(* Logix 5000 AddOnInstructionDefinition export Banner_T30RKD_Param_v4; software revision 32.00; part 2 of 3 *)
(* tags used below, declared in another part *)
   T30RKD : Banner_T30RKD_v3;
   Port_Data : Banner_IOL_Port_v4;
   Port : DINT;
   Local_Control : DINT;
   Command_Being_Processed : BOOL;
   Update_Archive : BOOL;
   Index_Write_Inprocess : DINT;
   Index_Write_Control : DINT;
   Inprocess_Index : DINT;
(* Banner_T30RKD_Param_v4, continued *)

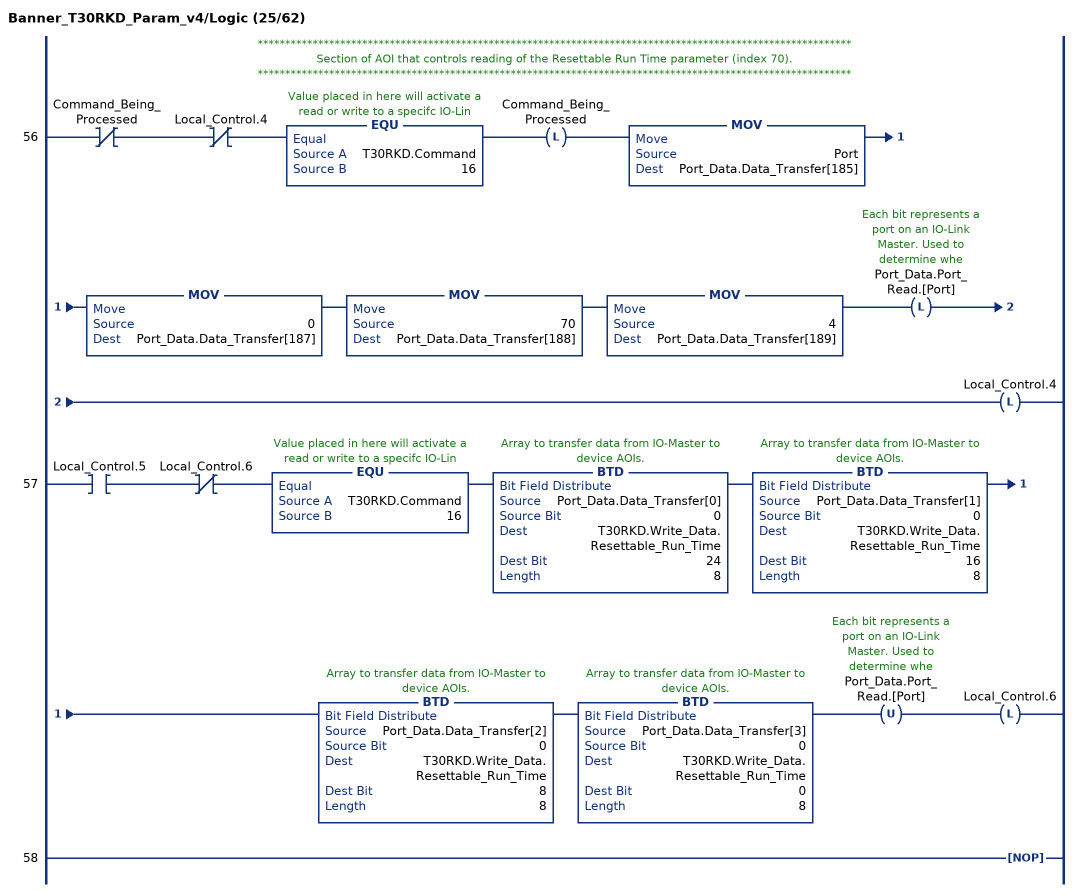
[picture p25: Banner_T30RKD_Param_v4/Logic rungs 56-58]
   // ************************************************************************************************************
   // Section of AOI that controls reading of the Resettable Run Time parameter (index 70).
   // ************************************************************************************************************
   56: XIO(Command_Being_Processed)XIO(Local_Control.4)EQU(T30RKD.Command,16)OTL(Command_Being_Processed)MOV(Port,Port_Data.Data_Transfer[185])MOV(0,Port_Data.Data_Transfer[187])MOV(70,Port_Data.Data_Transfer[188])MOV(4,Port_Data.Data_Transfer[189])OTL(Port_Data.Port_Read.[Port])OTL(Local_Control.4);
   57: XIC(Local_Control.5)XIO(Local_Control.6)EQU(T30RKD.Command,16)BTD(Port_Data.Data_Transfer[0],0,T30RKD.Write_Data.Resettable_Run_Time,24,8)BTD(Port_Data.Data_Transfer[1],0,T30RKD.Write_Data.Resettable_Run_Time,16,8)BTD(Port_Data.Data_Transfer[2],0,T30RKD.Write_Data.Resettable_Run_Time,8,8)BTD(Port_Data.Data_Transfer[3],0,T30RKD.Write_Data.Resettable_Run_Time,0,8)OTU(Port_Data.Port_Read.[Port])OTL(Local_Control.6);
   58: NOP();
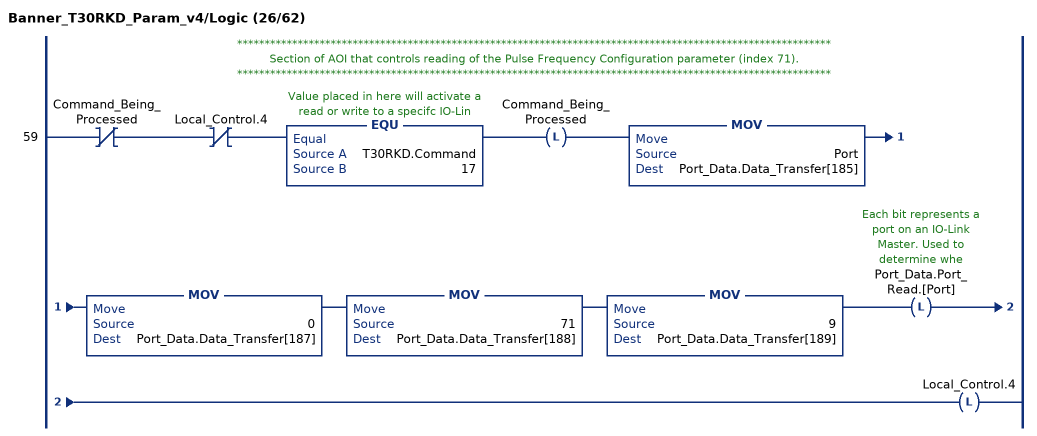
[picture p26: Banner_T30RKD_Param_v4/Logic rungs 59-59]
   // ************************************************************************************************************
   // Section of AOI that controls reading of the Pulse Frequency Configuration parameter (index 71).
   // ************************************************************************************************************
   59: XIO(Command_Being_Processed)XIO(Local_Control.4)EQU(T30RKD.Command,17)OTL(Command_Being_Processed)MOV(Port,Port_Data.Data_Transfer[185])MOV(0,Port_Data.Data_Transfer[187])MOV(71,Port_Data.Data_Transfer[188])MOV(9,Port_Data.Data_Transfer[189])OTL(Port_Data.Port_Read.[Port])OTL(Local_Control.4);
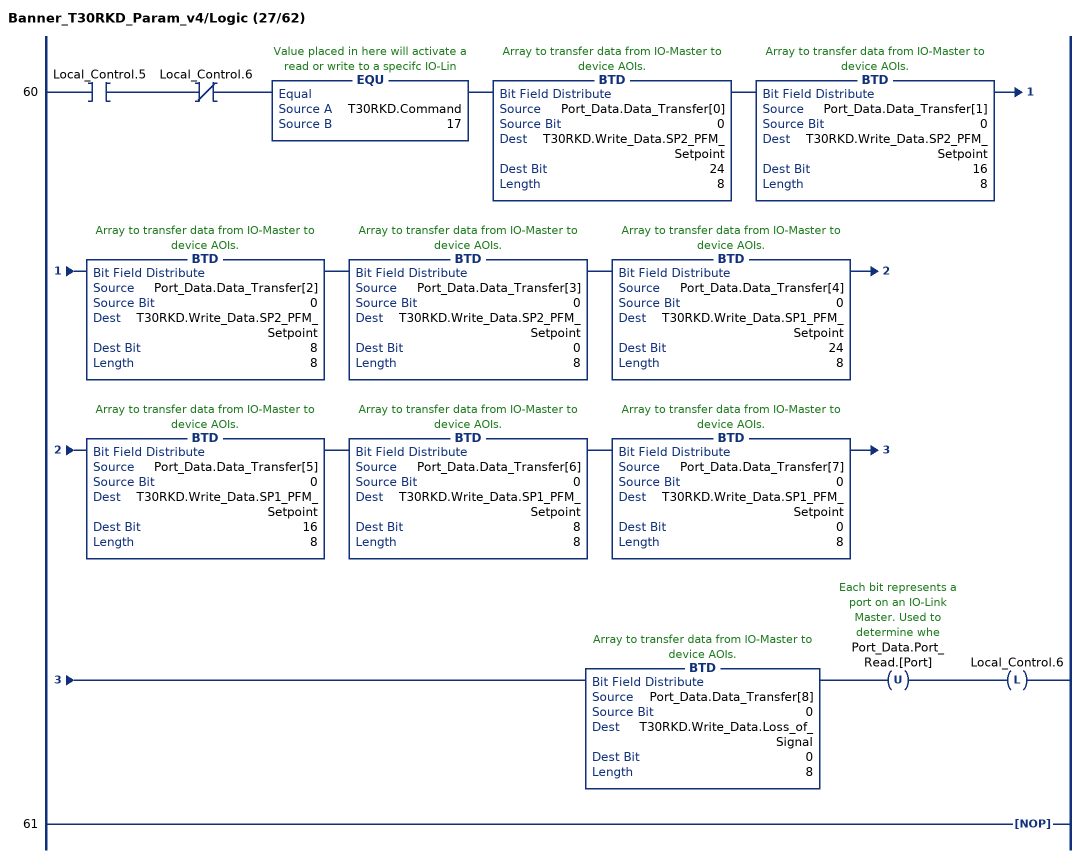
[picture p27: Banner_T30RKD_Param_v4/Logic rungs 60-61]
   60: XIC(Local_Control.5)XIO(Local_Control.6)EQU(T30RKD.Command,17)BTD(Port_Data.Data_Transfer[0],0,T30RKD.Write_Data.SP2_PFM_Setpoint,24,8)BTD(Port_Data.Data_Transfer[1],0,T30RKD.Write_Data.SP2_PFM_Setpoint,16,8)BTD(Port_Data.Data_Transfer[2],0,T30RKD.Write_Data.SP2_PFM_Setpoint,8,8)BTD(Port_Data.Data_Transfer[3],0,T30RKD.Write_Data.SP2_PFM_Setpoint,0,8)BTD(Port_Data.Data_Transfer[4],0,T30RKD.Write_Data.SP1_PFM_Setpoint,24,8)BTD(Port_Data.Data_Transfer[5],0,T30RKD.Write_Data.SP1_PFM_Setpoint,16,8)BTD(Port_Data.Data_Transfer[6],0,T30RKD.Write_Data.SP1_PFM_Setpoint,8,8)BTD(Port_Data.Data_Transfer[7],0,T30RKD.Write_Data.SP1_PFM_Setpoint,0,8)BTD(Port_Data.Data_Transfer[8],0,T30RKD.Write_Data.Loss_of_Signal,0,8)OTU(Port_Data.Port_Read.[Port])OTL(Local_Control.6);
   61: NOP();
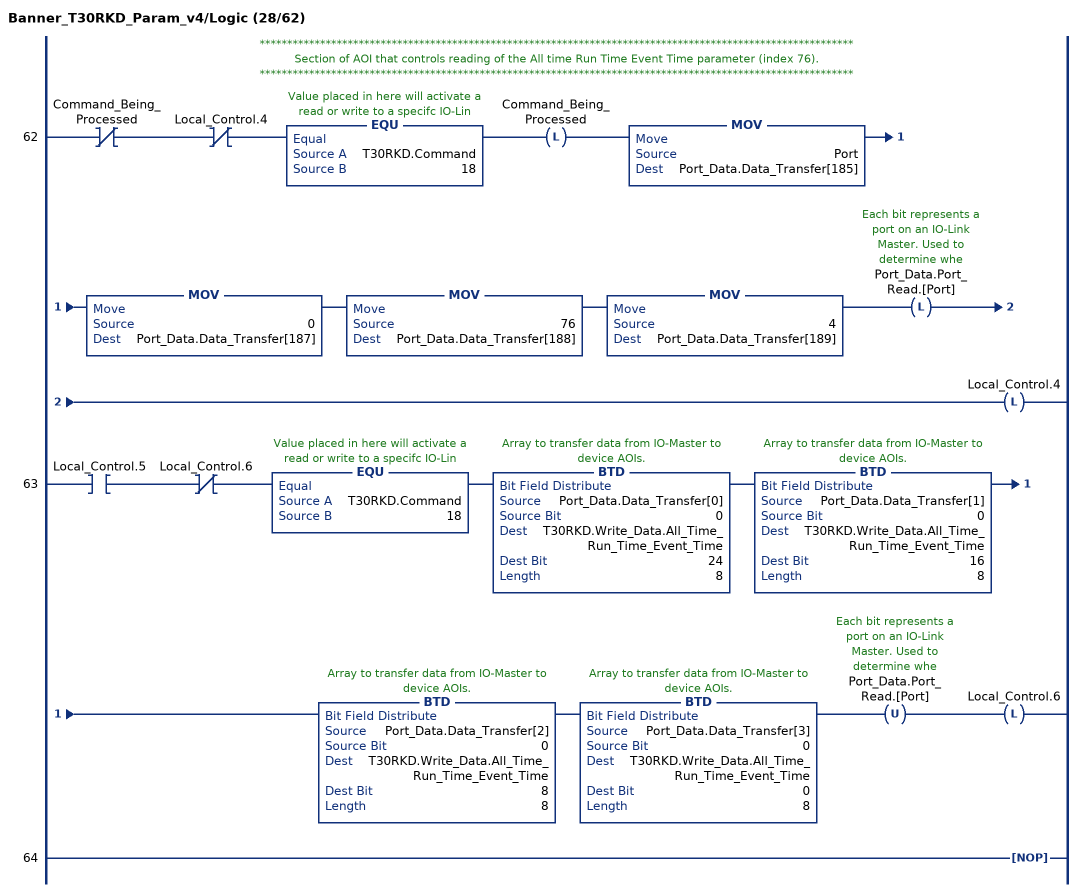
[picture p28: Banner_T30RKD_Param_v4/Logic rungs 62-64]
   // ************************************************************************************************************
   // Section of AOI that controls reading of the All time Run Time Event Time parameter (index 76).
   // ************************************************************************************************************
   62: XIO(Command_Being_Processed)XIO(Local_Control.4)EQU(T30RKD.Command,18)OTL(Command_Being_Processed)MOV(Port,Port_Data.Data_Transfer[185])MOV(0,Port_Data.Data_Transfer[187])MOV(76,Port_Data.Data_Transfer[188])MOV(4,Port_Data.Data_Transfer[189])OTL(Port_Data.Port_Read.[Port])OTL(Local_Control.4);
   63: XIC(Local_Control.5)XIO(Local_Control.6)EQU(T30RKD.Command,18)BTD(Port_Data.Data_Transfer[0],0,T30RKD.Write_Data.All_Time_Run_Time_Event_Time,24,8)BTD(Port_Data.Data_Transfer[1],0,T30RKD.Write_Data.All_Time_Run_Time_Event_Time,16,8)BTD(Port_Data.Data_Transfer[2],0,T30RKD.Write_Data.All_Time_Run_Time_Event_Time,8,8)BTD(Port_Data.Data_Transfer[3],0,T30RKD.Write_Data.All_Time_Run_Time_Event_Time,0,8)OTU(Port_Data.Port_Read.[Port])OTL(Local_Control.6);
   64: NOP();
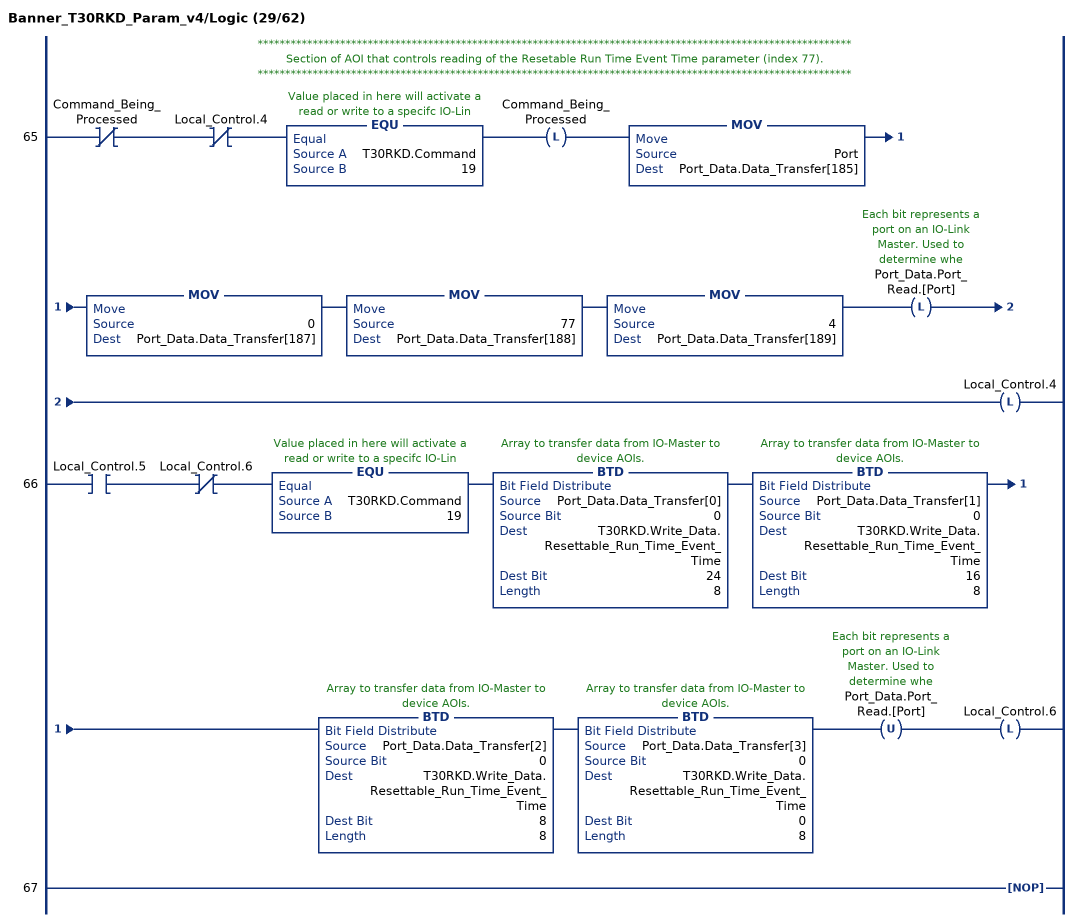
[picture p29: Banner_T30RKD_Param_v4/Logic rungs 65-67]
   // ************************************************************************************************************
   // Section of AOI that controls reading of the Resetable Run Time Event Time parameter (index 77).
   // ************************************************************************************************************
   65: XIO(Command_Being_Processed)XIO(Local_Control.4)EQU(T30RKD.Command,19)OTL(Command_Being_Processed)MOV(Port,Port_Data.Data_Transfer[185])MOV(0,Port_Data.Data_Transfer[187])MOV(77,Port_Data.Data_Transfer[188])MOV(4,Port_Data.Data_Transfer[189])OTL(Port_Data.Port_Read.[Port])OTL(Local_Control.4);
   66: XIC(Local_Control.5)XIO(Local_Control.6)EQU(T30RKD.Command,19)BTD(Port_Data.Data_Transfer[0],0,T30RKD.Write_Data.Resettable_Run_Time_Event_Time,24,8)BTD(Port_Data.Data_Transfer[1],0,T30RKD.Write_Data.Resettable_Run_Time_Event_Time,16,8)BTD(Port_Data.Data_Transfer[2],0,T30RKD.Write_Data.Resettable_Run_Time_Event_Time,8,8)BTD(Port_Data.Data_Transfer[3],0,T30RKD.Write_Data.Resettable_Run_Time_Event_Time,0,8)OTU(Port_Data.Port_Read.[Port])OTL(Local_Control.6);
   67: NOP();
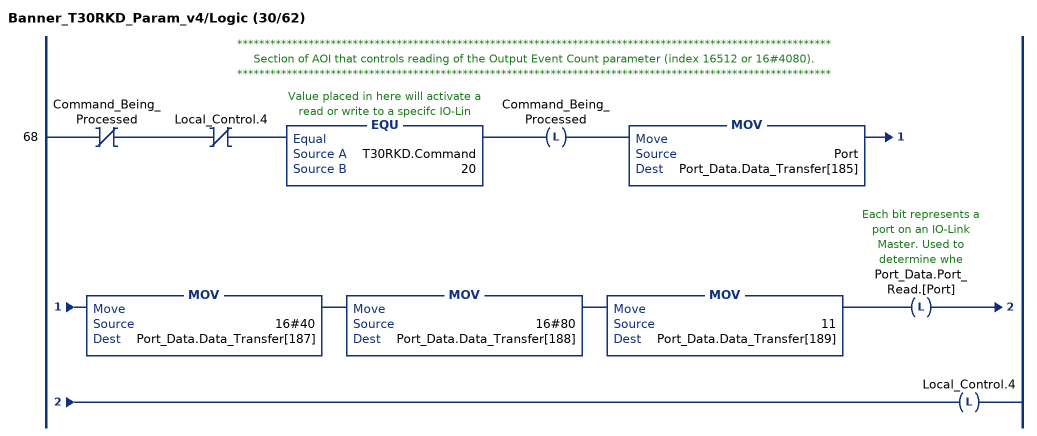
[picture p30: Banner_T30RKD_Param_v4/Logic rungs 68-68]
   // ************************************************************************************************************
   // Section of AOI that controls reading of the Output Event Count parameter (index 16512 or 16#4080).
   // ************************************************************************************************************
   68: XIO(Command_Being_Processed)XIO(Local_Control.4)EQU(T30RKD.Command,20)OTL(Command_Being_Processed)MOV(Port,Port_Data.Data_Transfer[185])MOV(16#40,Port_Data.Data_Transfer[187])MOV(16#80,Port_Data.Data_Transfer[188])MOV(11,Port_Data.Data_Transfer[189])OTL(Port_Data.Port_Read.[Port])OTL(Local_Control.4);
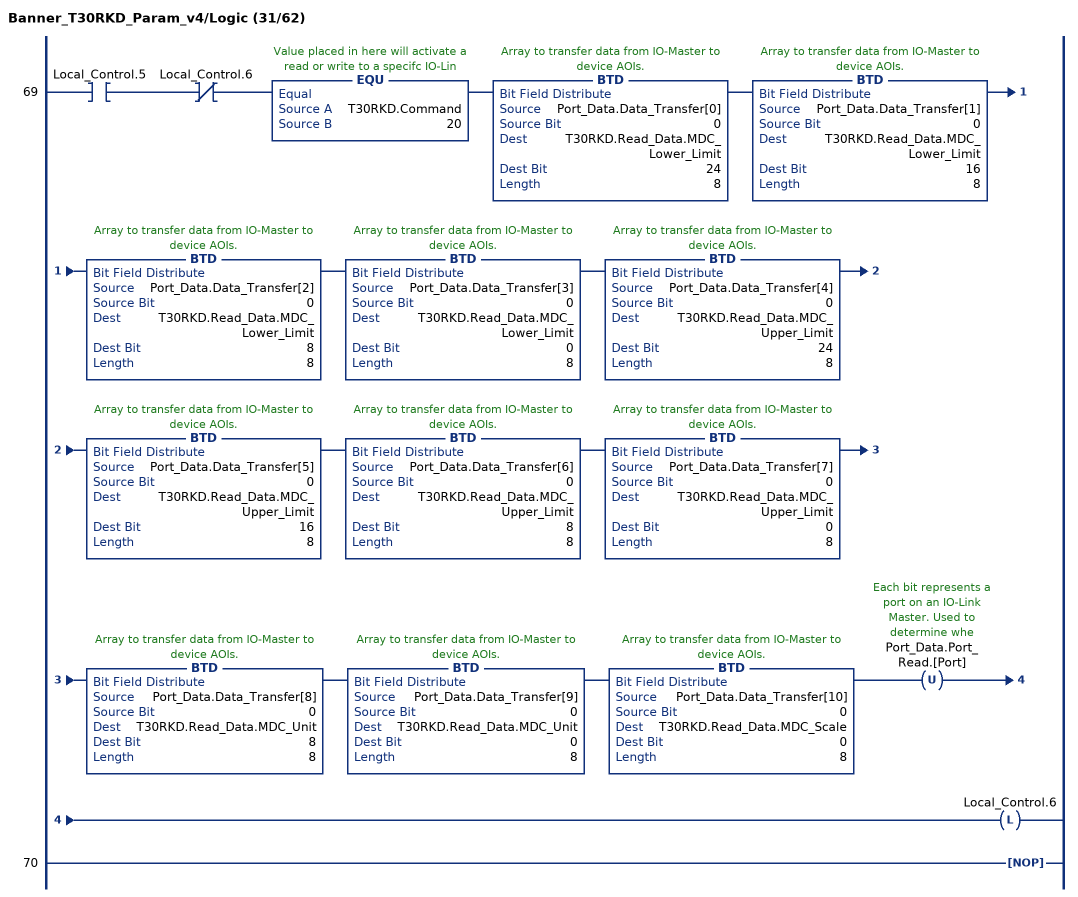
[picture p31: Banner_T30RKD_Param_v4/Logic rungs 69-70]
   69: XIC(Local_Control.5)XIO(Local_Control.6)EQU(T30RKD.Command,20)BTD(Port_Data.Data_Transfer[0],0,T30RKD.Read_Data.MDC_Lower_Limit,24,8)BTD(Port_Data.Data_Transfer[1],0,T30RKD.Read_Data.MDC_Lower_Limit,16,8)BTD(Port_Data.Data_Transfer[2],0,T30RKD.Read_Data.MDC_Lower_Limit,8,8)BTD(Port_Data.Data_Transfer[3],0,T30RKD.Read_Data.MDC_Lower_Limit,0,8)BTD(Port_Data.Data_Transfer[4],0,T30RKD.Read_Data.MDC_Upper_Limit,24,8)BTD(Port_Data.Data_Transfer[5],0,T30RKD.Read_Data.MDC_Upper_Limit,16,8)BTD(Port_Data.Data_Transfer[6],0,T30RKD.Read_Data.MDC_Upper_Limit,8,8)BTD(Port_Data.Data_Transfer[7],0,T30RKD.Read_Data.MDC_Upper_Limit,0,8)BTD(Port_Data.Data_Transfer[8],0,T30RKD.Read_Data.MDC_Unit,8,8)BTD(Port_Data.Data_Transfer[9],0,T30RKD.Read_Data.MDC_Unit,0,8)BTD(Port_Data.Data_Transfer[10],0,T30RKD.Read_Data.MDC_Scale,0,8)OTU(Port_Data.Port_Read.[Port])OTL(Local_Control.6);
   70: NOP();
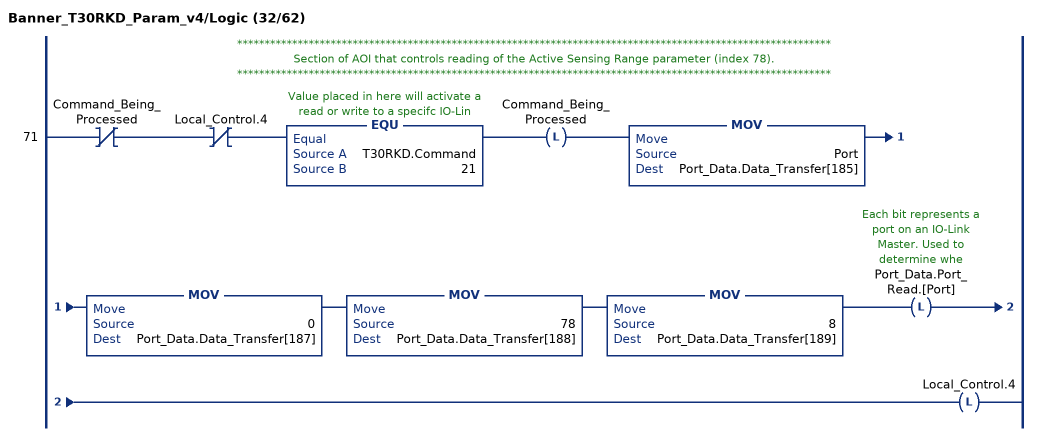
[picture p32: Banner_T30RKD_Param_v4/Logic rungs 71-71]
   // ************************************************************************************************************
   // Section of AOI that controls reading of the Active Sensing Range parameter (index 78).
   // ************************************************************************************************************
   71: XIO(Command_Being_Processed)XIO(Local_Control.4)EQU(T30RKD.Command,21)OTL(Command_Being_Processed)MOV(Port,Port_Data.Data_Transfer[185])MOV(0,Port_Data.Data_Transfer[187])MOV(78,Port_Data.Data_Transfer[188])MOV(8,Port_Data.Data_Transfer[189])OTL(Port_Data.Port_Read.[Port])OTL(Local_Control.4);
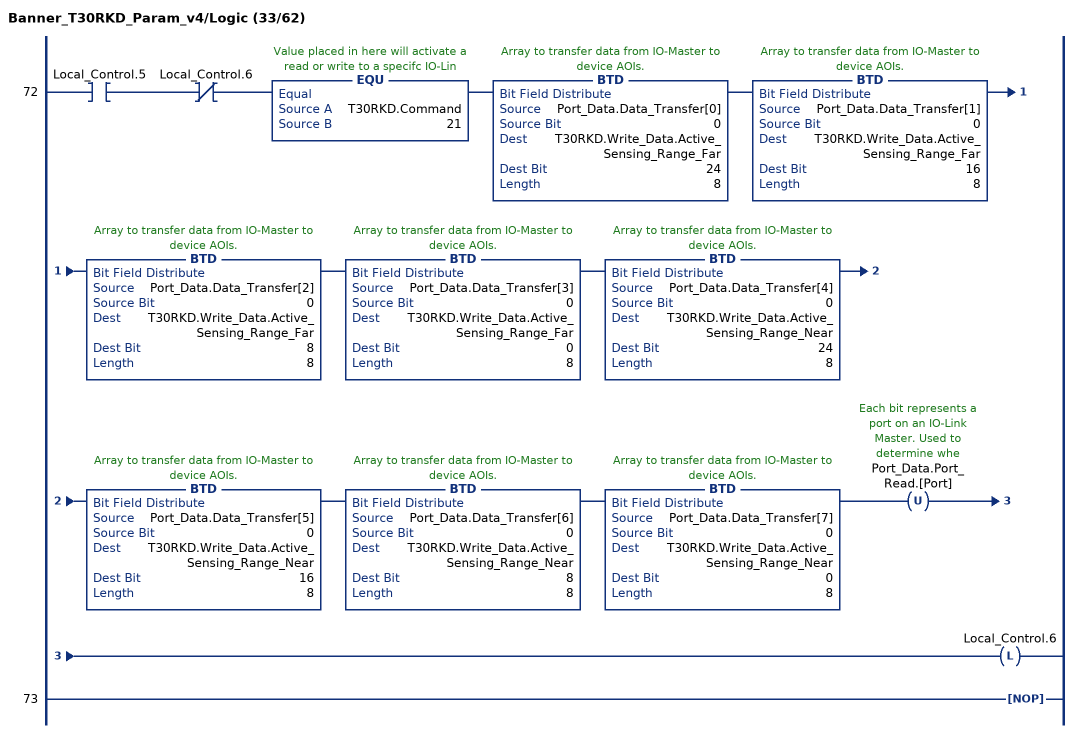
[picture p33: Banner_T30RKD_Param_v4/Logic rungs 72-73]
   72: XIC(Local_Control.5)XIO(Local_Control.6)EQU(T30RKD.Command,21)BTD(Port_Data.Data_Transfer[0],0,T30RKD.Write_Data.Active_Sensing_Range_Far,24,8)BTD(Port_Data.Data_Transfer[1],0,T30RKD.Write_Data.Active_Sensing_Range_Far,16,8)BTD(Port_Data.Data_Transfer[2],0,T30RKD.Write_Data.Active_Sensing_Range_Far,8,8)BTD(Port_Data.Data_Transfer[3],0,T30RKD.Write_Data.Active_Sensing_Range_Far,0,8)BTD(Port_Data.Data_Transfer[4],0,T30RKD.Write_Data.Active_Sensing_Range_Near,24,8)BTD(Port_Data.Data_Transfer[5],0,T30RKD.Write_Data.Active_Sensing_Range_Near,16,8)BTD(Port_Data.Data_Transfer[6],0,T30RKD.Write_Data.Active_Sensing_Range_Near,8,8)BTD(Port_Data.Data_Transfer[7],0,T30RKD.Write_Data.Active_Sensing_Range_Near,0,8)OTU(Port_Data.Port_Read.[Port])OTL(Local_Control.6);
   73: NOP();
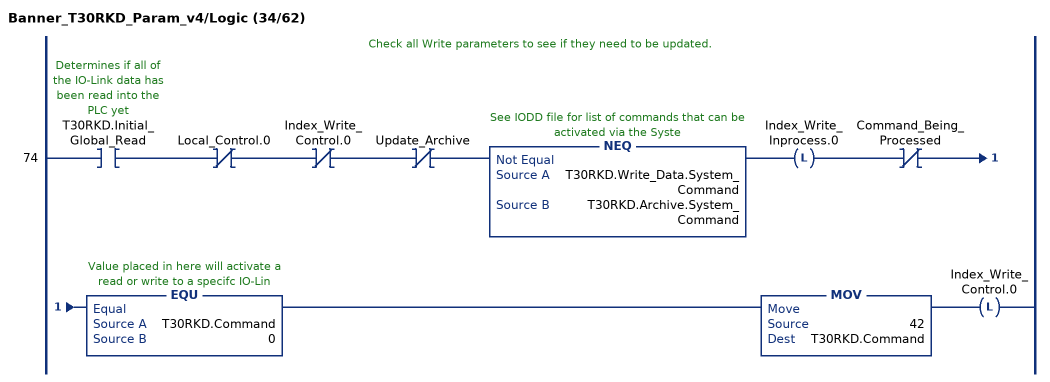
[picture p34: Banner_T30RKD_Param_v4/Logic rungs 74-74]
   // Check all Write parameters to see if they need to be updated.
   74: XIC(T30RKD.Initial_Global_Read)XIO(Local_Control.0)XIO(Index_Write_Control.0)XIO(Update_Archive)NEQ(T30RKD.Write_Data.System_Command,T30RKD.Archive.System_Command)OTL(Index_Write_Inprocess.0)XIO(Command_Being_Processed)EQU(T30RKD.Command,0)MOV(42,T30RKD.Command)OTL(Index_Write_Control.0);
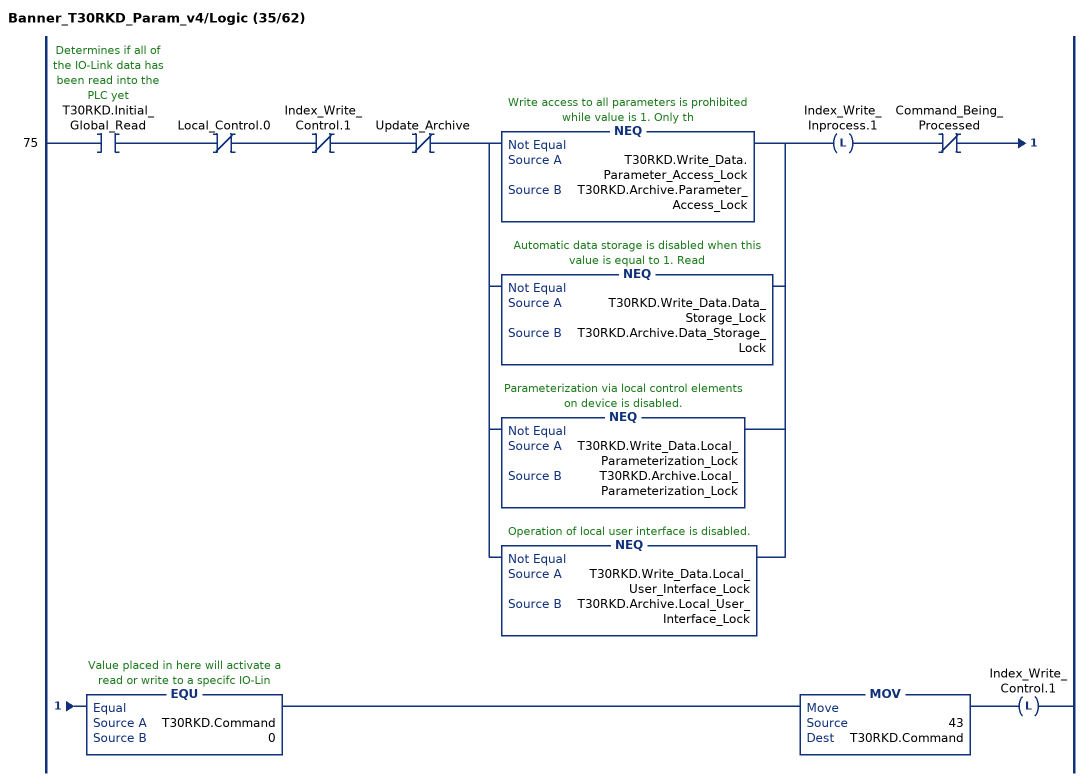
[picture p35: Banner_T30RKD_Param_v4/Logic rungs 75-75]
   75: XIC(T30RKD.Initial_Global_Read)XIO(Local_Control.0)XIO(Index_Write_Control.1)XIO(Update_Archive)[NEQ(T30RKD.Write_Data.Parameter_Access_Lock,T30RKD.Archive.Parameter_Access_Lock) ,NEQ(T30RKD.Write_Data.Data_Storage_Lock,T30RKD.Archive.Data_Storage_Lock) ,NEQ(T30RKD.Write_Data.Local_Parameterization_Lock,T30RKD.Archive.Local_Parameterization_Lock) ,NEQ(T30RKD.Write_Data.Local_User_Interface_Lock,T30RKD.Archive.Local_User_Interface_Lock) ]OTL(Index_Write_Inprocess.1)XIO(Command_Being_Processed)EQU(T30RKD.Command,0)MOV(43,T30RKD.Command)OTL(Index_Write_Control.1);
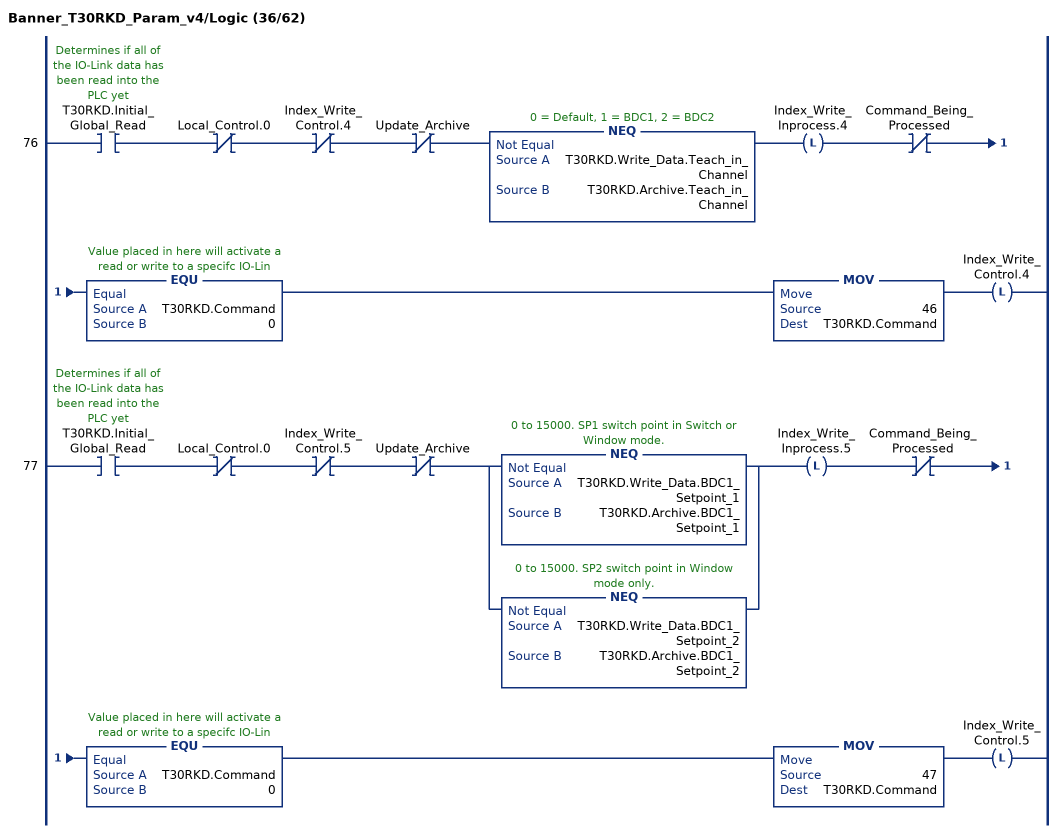
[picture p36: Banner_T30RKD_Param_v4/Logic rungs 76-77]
   76: XIC(T30RKD.Initial_Global_Read)XIO(Local_Control.0)XIO(Index_Write_Control.4)XIO(Update_Archive)NEQ(T30RKD.Write_Data.Teach_in_Channel,T30RKD.Archive.Teach_in_Channel)OTL(Index_Write_Inprocess.4)XIO(Command_Being_Processed)EQU(T30RKD.Command,0)MOV(46,T30RKD.Command)OTL(Index_Write_Control.4);
   77: XIC(T30RKD.Initial_Global_Read)XIO(Local_Control.0)XIO(Index_Write_Control.5)XIO(Update_Archive)[NEQ(T30RKD.Write_Data.BDC1_Setpoint_1,T30RKD.Archive.BDC1_Setpoint_1) ,NEQ(T30RKD.Write_Data.BDC1_Setpoint_2,T30RKD.Archive.BDC1_Setpoint_2) ]OTL(Index_Write_Inprocess.5)XIO(Command_Being_Processed)EQU(T30RKD.Command,0)MOV(47,T30RKD.Command)OTL(Index_Write_Control.5);
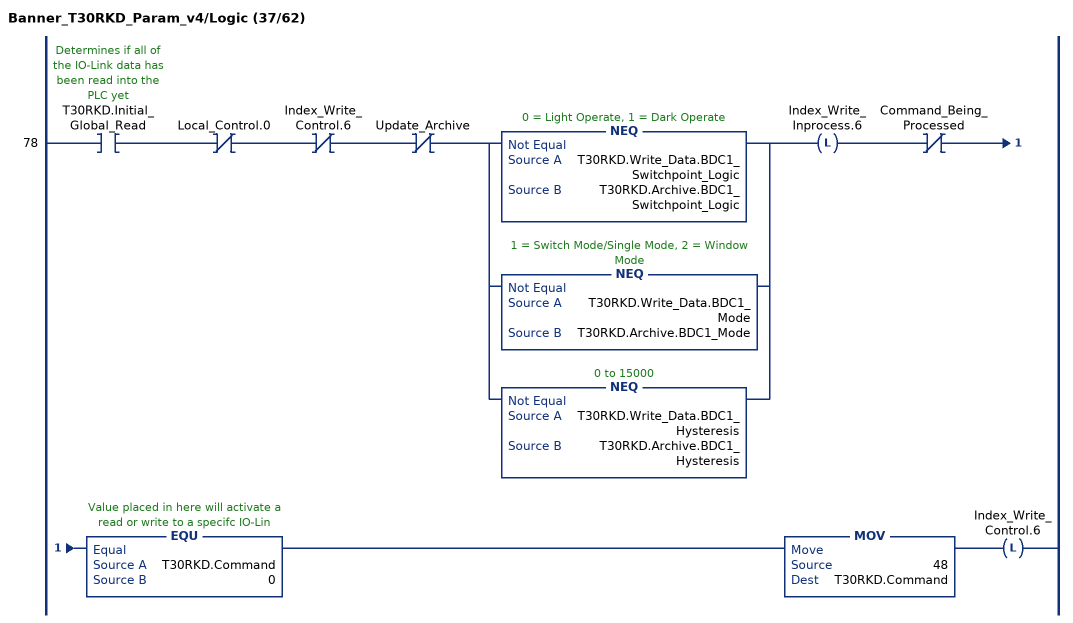
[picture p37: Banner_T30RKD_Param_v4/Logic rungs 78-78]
   78: XIC(T30RKD.Initial_Global_Read)XIO(Local_Control.0)XIO(Index_Write_Control.6)XIO(Update_Archive)[NEQ(T30RKD.Write_Data.BDC1_Switchpoint_Logic,T30RKD.Archive.BDC1_Switchpoint_Logic) ,NEQ(T30RKD.Write_Data.BDC1_Mode,T30RKD.Archive.BDC1_Mode) ,NEQ(T30RKD.Write_Data.BDC1_Hysteresis,T30RKD.Archive.BDC1_Hysteresis) ]OTL(Index_Write_Inprocess.6)XIO(Command_Being_Processed)EQU(T30RKD.Command,0)MOV(48,T30RKD.Command)OTL(Index_Write_Control.6);
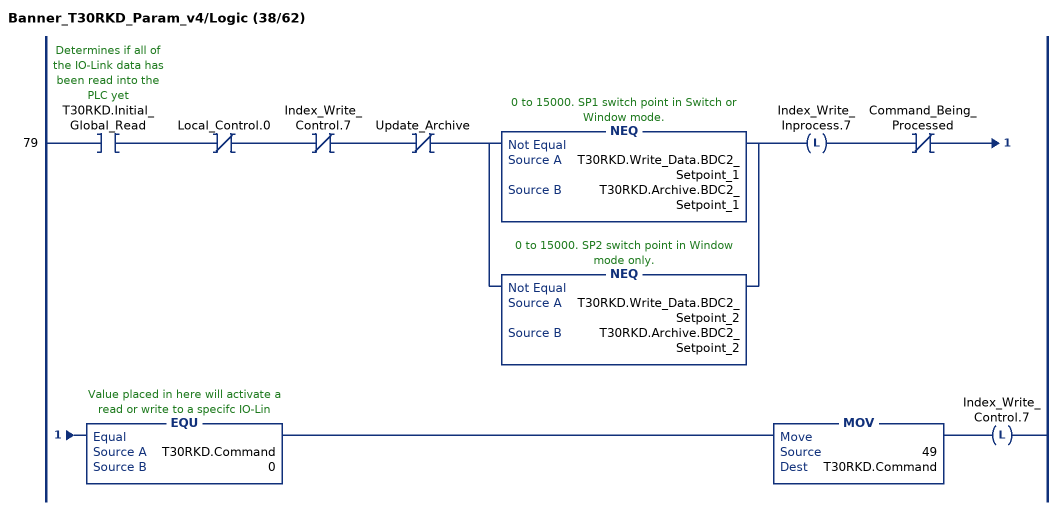
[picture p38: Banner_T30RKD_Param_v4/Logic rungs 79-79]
   79: XIC(T30RKD.Initial_Global_Read)XIO(Local_Control.0)XIO(Index_Write_Control.7)XIO(Update_Archive)[NEQ(T30RKD.Write_Data.BDC2_Setpoint_1,T30RKD.Archive.BDC2_Setpoint_1) ,NEQ(T30RKD.Write_Data.BDC2_Setpoint_2,T30RKD.Archive.BDC2_Setpoint_2) ]OTL(Index_Write_Inprocess.7)XIO(Command_Being_Processed)EQU(T30RKD.Command,0)MOV(49,T30RKD.Command)OTL(Index_Write_Control.7);
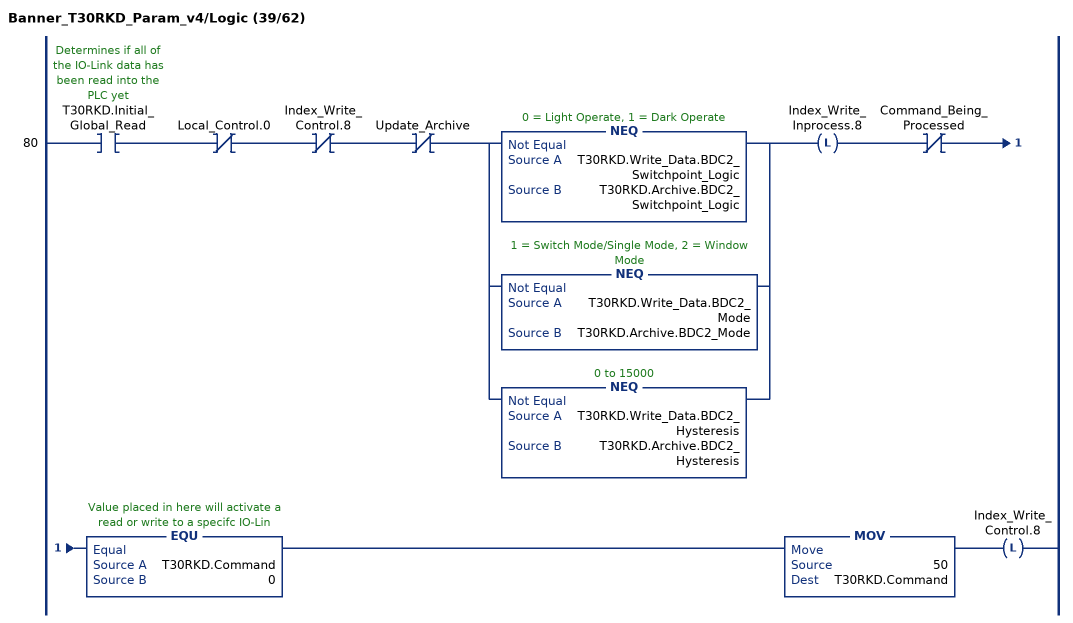
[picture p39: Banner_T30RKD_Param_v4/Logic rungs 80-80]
   80: XIC(T30RKD.Initial_Global_Read)XIO(Local_Control.0)XIO(Index_Write_Control.8)XIO(Update_Archive)[NEQ(T30RKD.Write_Data.BDC2_Switchpoint_Logic,T30RKD.Archive.BDC2_Switchpoint_Logic) ,NEQ(T30RKD.Write_Data.BDC2_Mode,T30RKD.Archive.BDC2_Mode) ,NEQ(T30RKD.Write_Data.BDC2_Hysteresis,T30RKD.Archive.BDC2_Hysteresis) ]OTL(Index_Write_Inprocess.8)XIO(Command_Being_Processed)EQU(T30RKD.Command,0)MOV(50,T30RKD.Command)OTL(Index_Write_Control.8);
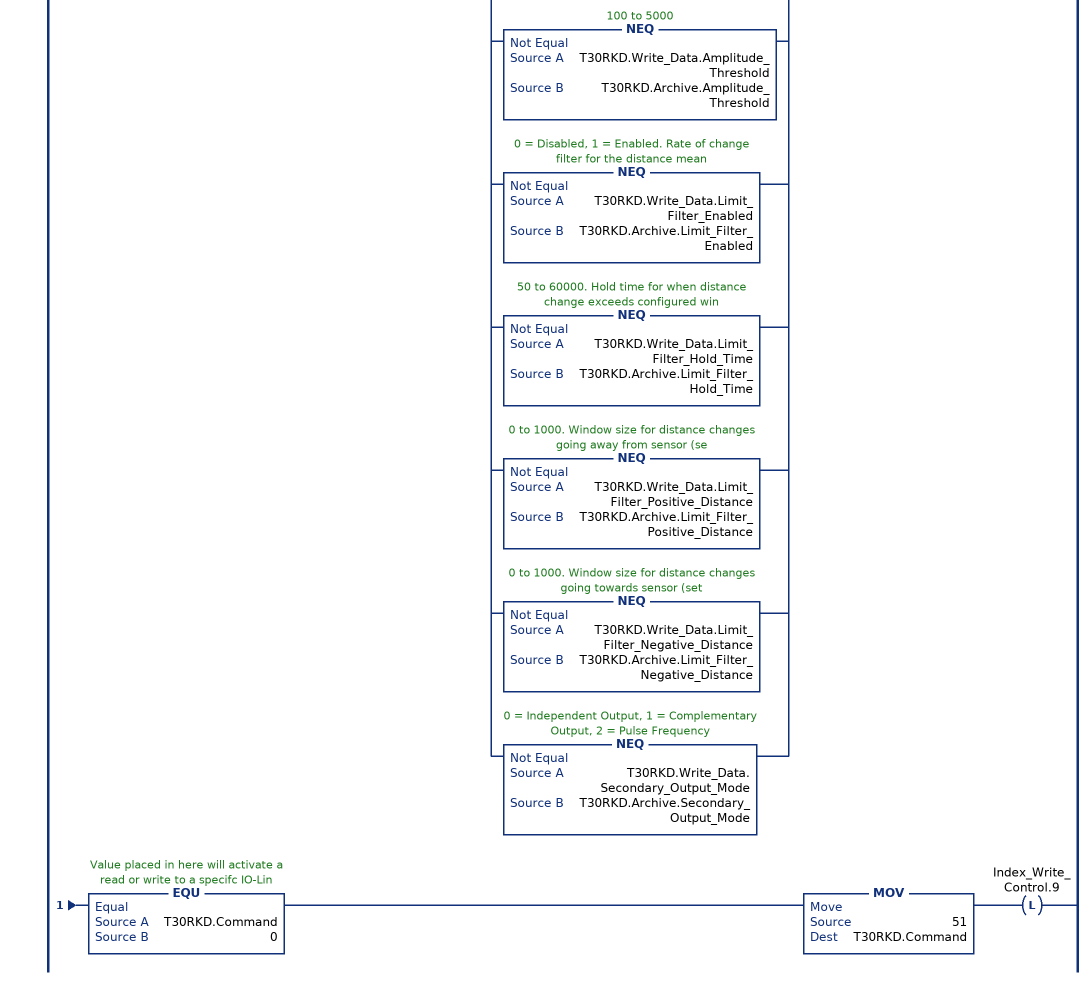
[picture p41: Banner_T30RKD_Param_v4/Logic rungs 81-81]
   81: XIC(T30RKD.Initial_Global_Read)XIO(Local_Control.0)XIO(Index_Write_Control.9)XIO(Update_Archive)[NEQ(T30RKD.Write_Data.Response_Speed,T30RKD.Archive.Response_Speed) ,NEQ(T30RKD.Write_Data.Peak_Select_Mode,T30RKD.Archive.Peak_Select_Mode) ,NEQ(T30RKD.Write_Data.Sensor_Lockout,T30RKD.Archive.Sensor_Lockout) ,NEQ(T30RKD.Write_Data.Output_Polarity,T30RKD.Archive.Output_Polarity) ,NEQ(T30RKD.Write_Data.Process_Data_Filter_Time,T30RKD.Archive.Process_Data_Filter_Time) ,NEQ(T30RKD.Write_Data.Process_Data_Layout,T30RKD.Archive.Process_Data_Layout) ,NEQ(T30RKD.Write_Data.Remote_Input_Mode,T30RKD.Archive.Remote_Input_Mode) ,NEQ(T30RKD.Write_Data.Amplitude_Threshold,T30RKD.Archive.Amplitude_Threshold) ,NEQ(T30RKD.Write_Data.Limit_Filter_Enabled,T30RKD.Archive.Limit_Filter_Enabled) ,NEQ(T30RKD.Write_Data.Limit_Filter_Hold_Time,T30RKD.Archive.Limit_Filter_Hold_Time) ,NEQ(T30RKD.Write_Data.Limit_Filter_Positive_Distance,T30RKD.Archive.Limit_Filter_Positive_Distance) ,NEQ(T30RKD.Write_Data.Limit_Filter_Negative_Distance,T30RKD.Archive.Limit_Filter_Negative_Distance) ,NEQ(T30RKD.Write_Data.Secondary_Output_Mode,T30RKD.Archive.Secondary_Output_Mode) ]OTL(Index_Write_Inprocess.9)XIO(Command_Being_Processed)EQU(T30RKD.Command,0)MOV(51,T30RKD.Command)OTL(Index_Write_Control.9);
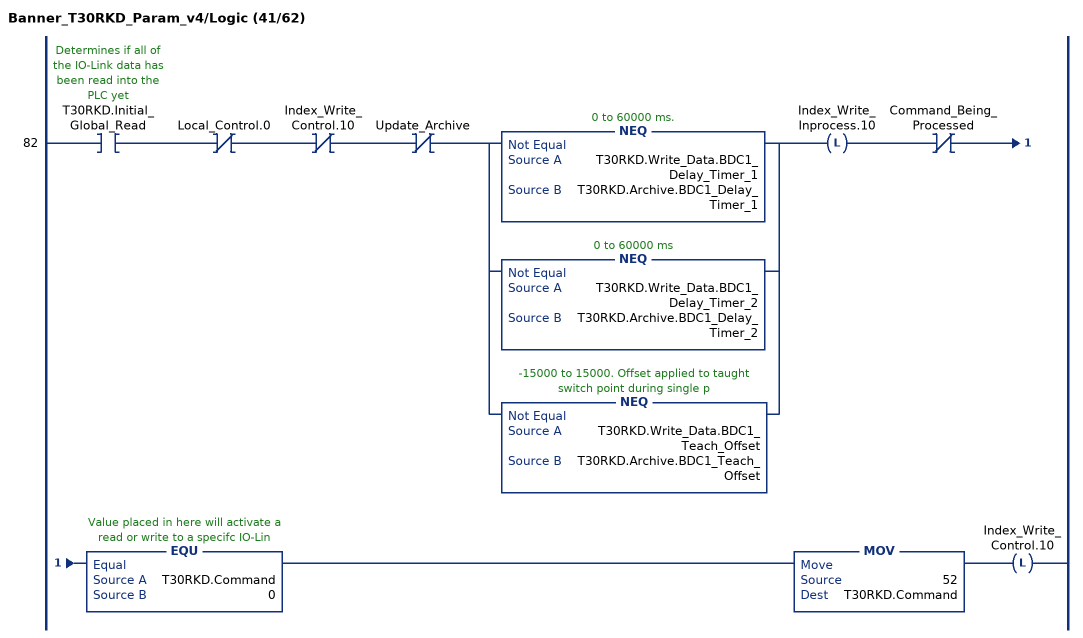
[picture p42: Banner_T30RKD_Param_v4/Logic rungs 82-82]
   82: XIC(T30RKD.Initial_Global_Read)XIO(Local_Control.0)XIO(Index_Write_Control.10)XIO(Update_Archive)[NEQ(T30RKD.Write_Data.BDC1_Delay_Timer_1,T30RKD.Archive.BDC1_Delay_Timer_1) ,NEQ(T30RKD.Write_Data.BDC1_Delay_Timer_2,T30RKD.Archive.BDC1_Delay_Timer_2) ,NEQ(T30RKD.Write_Data.BDC1_Teach_Offset,T30RKD.Archive.BDC1_Teach_Offset) ]OTL(Index_Write_Inprocess.10)XIO(Command_Being_Processed)EQU(T30RKD.Command,0)MOV(52,T30RKD.Command)OTL(Index_Write_Control.10);
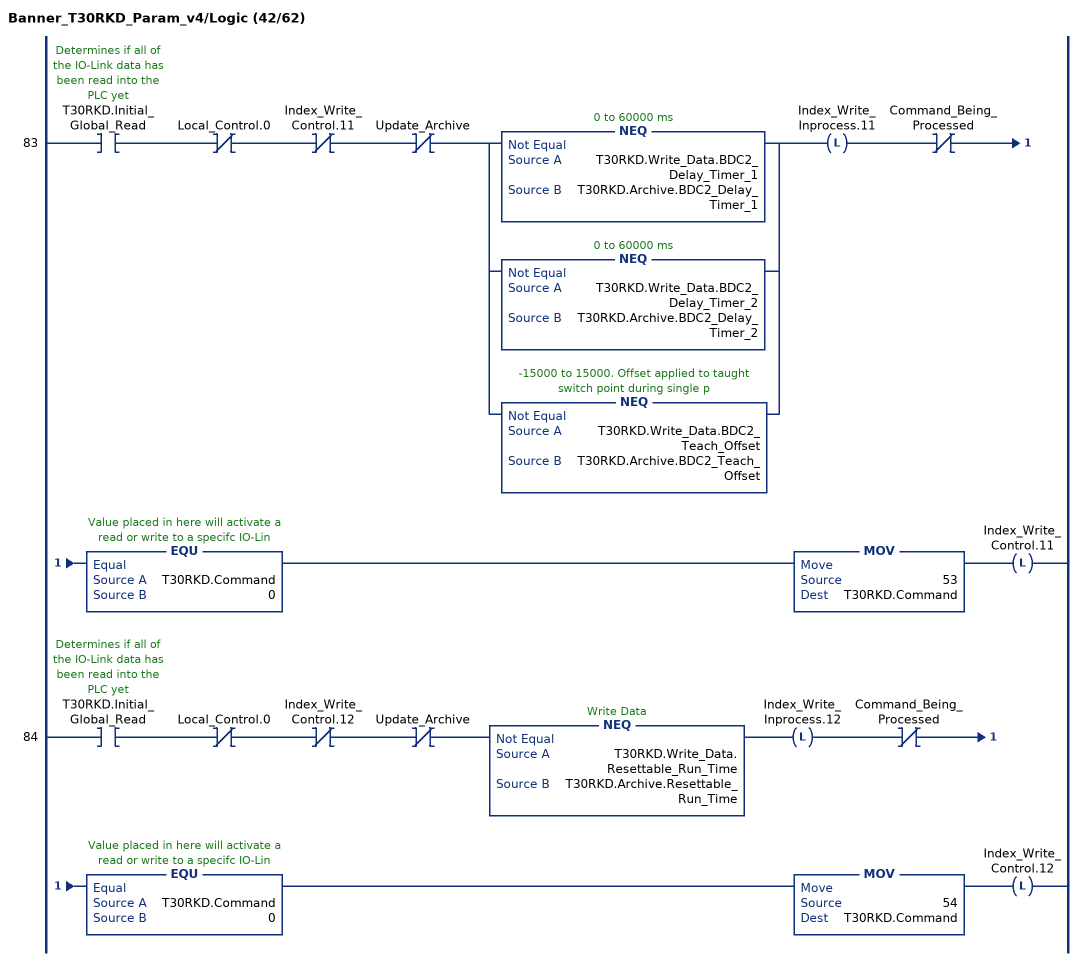
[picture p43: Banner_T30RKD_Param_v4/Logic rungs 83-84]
   83: XIC(T30RKD.Initial_Global_Read)XIO(Local_Control.0)XIO(Index_Write_Control.11)XIO(Update_Archive)[NEQ(T30RKD.Write_Data.BDC2_Delay_Timer_1,T30RKD.Archive.BDC2_Delay_Timer_1) ,NEQ(T30RKD.Write_Data.BDC2_Delay_Timer_2,T30RKD.Archive.BDC2_Delay_Timer_2) ,NEQ(T30RKD.Write_Data.BDC2_Teach_Offset,T30RKD.Archive.BDC2_Teach_Offset) ]OTL(Index_Write_Inprocess.11)XIO(Command_Being_Processed)EQU(T30RKD.Command,0)MOV(53,T30RKD.Command)OTL(Index_Write_Control.11);
   84: XIC(T30RKD.Initial_Global_Read)XIO(Local_Control.0)XIO(Index_Write_Control.12)XIO(Update_Archive)NEQ(T30RKD.Write_Data.Resettable_Run_Time,T30RKD.Archive.Resettable_Run_Time)OTL(Index_Write_Inprocess.12)XIO(Command_Being_Processed)EQU(T30RKD.Command,0)MOV(54,T30RKD.Command)OTL(Index_Write_Control.12);
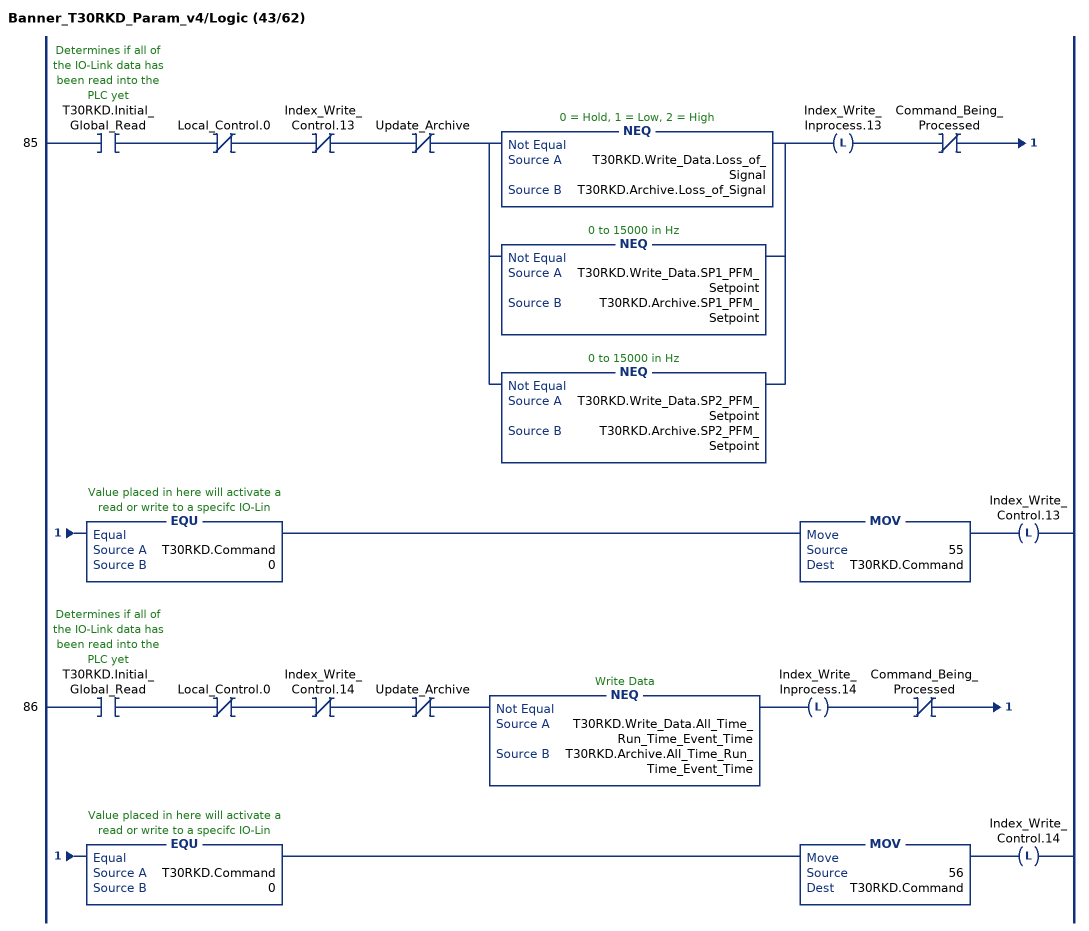
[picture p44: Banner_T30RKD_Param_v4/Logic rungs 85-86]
   85: XIC(T30RKD.Initial_Global_Read)XIO(Local_Control.0)XIO(Index_Write_Control.13)XIO(Update_Archive)[NEQ(T30RKD.Write_Data.Loss_of_Signal,T30RKD.Archive.Loss_of_Signal) ,NEQ(T30RKD.Write_Data.SP1_PFM_Setpoint,T30RKD.Archive.SP1_PFM_Setpoint) ,NEQ(T30RKD.Write_Data.SP2_PFM_Setpoint,T30RKD.Archive.SP2_PFM_Setpoint) ]OTL(Index_Write_Inprocess.13)XIO(Command_Being_Processed)EQU(T30RKD.Command,0)MOV(55,T30RKD.Command)OTL(Index_Write_Control.13);
   86: XIC(T30RKD.Initial_Global_Read)XIO(Local_Control.0)XIO(Index_Write_Control.14)XIO(Update_Archive)NEQ(T30RKD.Write_Data.All_Time_Run_Time_Event_Time,T30RKD.Archive.All_Time_Run_Time_Event_Time)OTL(Index_Write_Inprocess.14)XIO(Command_Being_Processed)EQU(T30RKD.Command,0)MOV(56,T30RKD.Command)OTL(Index_Write_Control.14);
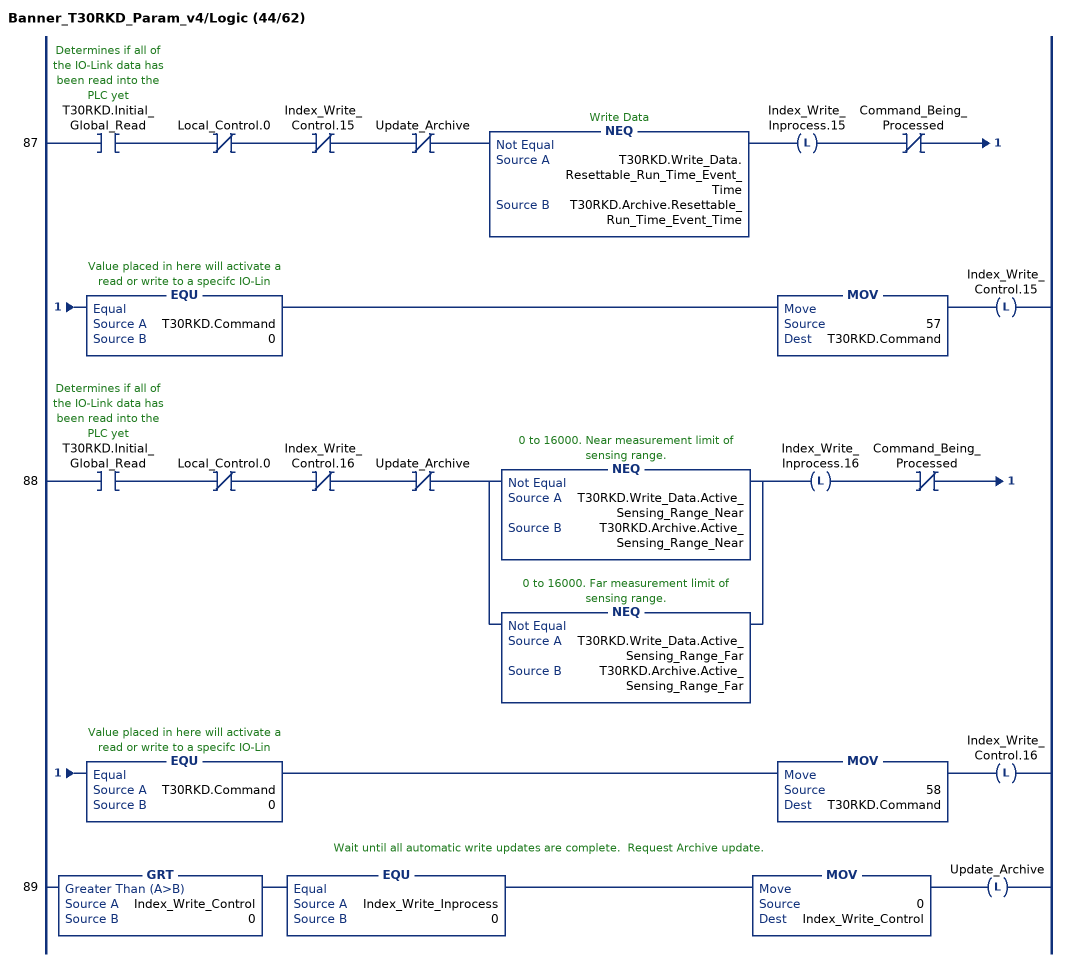
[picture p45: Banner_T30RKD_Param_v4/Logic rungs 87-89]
   87: XIC(T30RKD.Initial_Global_Read)XIO(Local_Control.0)XIO(Index_Write_Control.15)XIO(Update_Archive)NEQ(T30RKD.Write_Data.Resettable_Run_Time_Event_Time,T30RKD.Archive.Resettable_Run_Time_Event_Time)OTL(Index_Write_Inprocess.15)XIO(Command_Being_Processed)EQU(T30RKD.Command,0)MOV(57,T30RKD.Command)OTL(Index_Write_Control.15);
   88: XIC(T30RKD.Initial_Global_Read)XIO(Local_Control.0)XIO(Index_Write_Control.16)XIO(Update_Archive)[NEQ(T30RKD.Write_Data.Active_Sensing_Range_Near,T30RKD.Archive.Active_Sensing_Range_Near) ,NEQ(T30RKD.Write_Data.Active_Sensing_Range_Far,T30RKD.Archive.Active_Sensing_Range_Far) ]OTL(Index_Write_Inprocess.16)XIO(Command_Being_Processed)EQU(T30RKD.Command,0)MOV(58,T30RKD.Command)OTL(Index_Write_Control.16);
   // Wait until all automatic write updates are complete.  Request Archive update.
   89: GRT(Index_Write_Control,0)EQU(Index_Write_Inprocess,0)MOV(0,Index_Write_Control)OTL(Update_Archive);
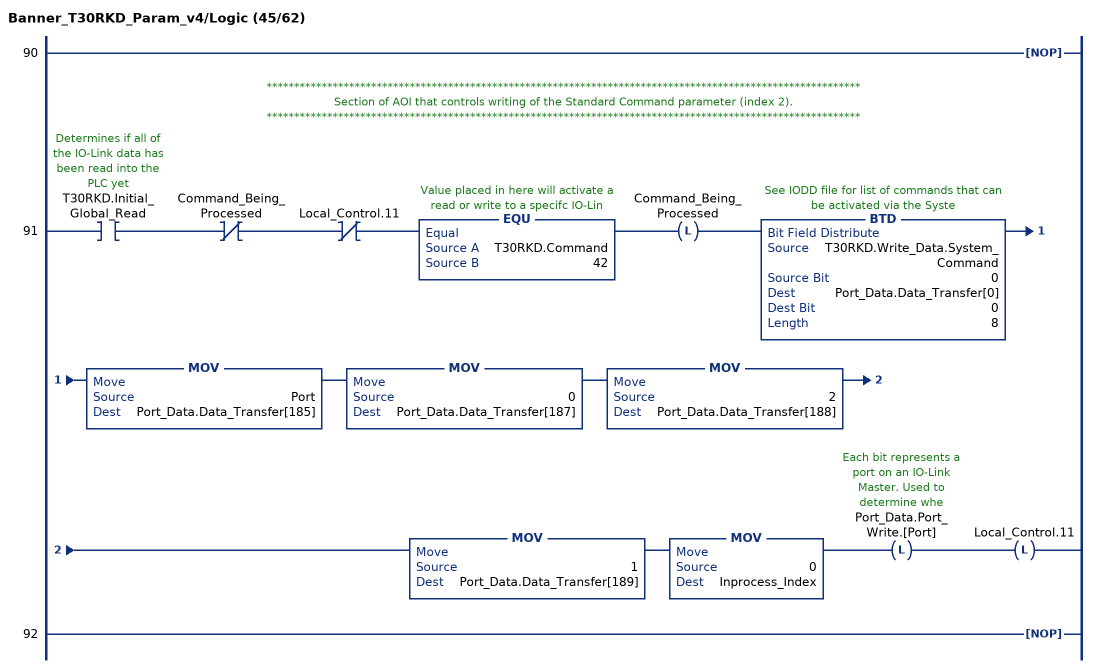
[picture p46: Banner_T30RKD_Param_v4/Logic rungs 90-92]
   90: NOP();
   // ************************************************************************************************************
   // Section of AOI that controls writing of the Standard Command parameter (index 2).
   // ************************************************************************************************************
   91: XIC(T30RKD.Initial_Global_Read)XIO(Command_Being_Processed)XIO(Local_Control.11)EQU(T30RKD.Command,42)OTL(Command_Being_Processed)BTD(T30RKD.Write_Data.System_Command,0,Port_Data.Data_Transfer[0],0,8)MOV(Port,Port_Data.Data_Transfer[185])MOV(0,Port_Data.Data_Transfer[187])MOV(2,Port_Data.Data_Transfer[188])MOV(1,Port_Data.Data_Transfer[189])MOV(0,Inprocess_Index)OTL(Port_Data.Port_Write.[Port])OTL(Local_Control.11);
   92: NOP();
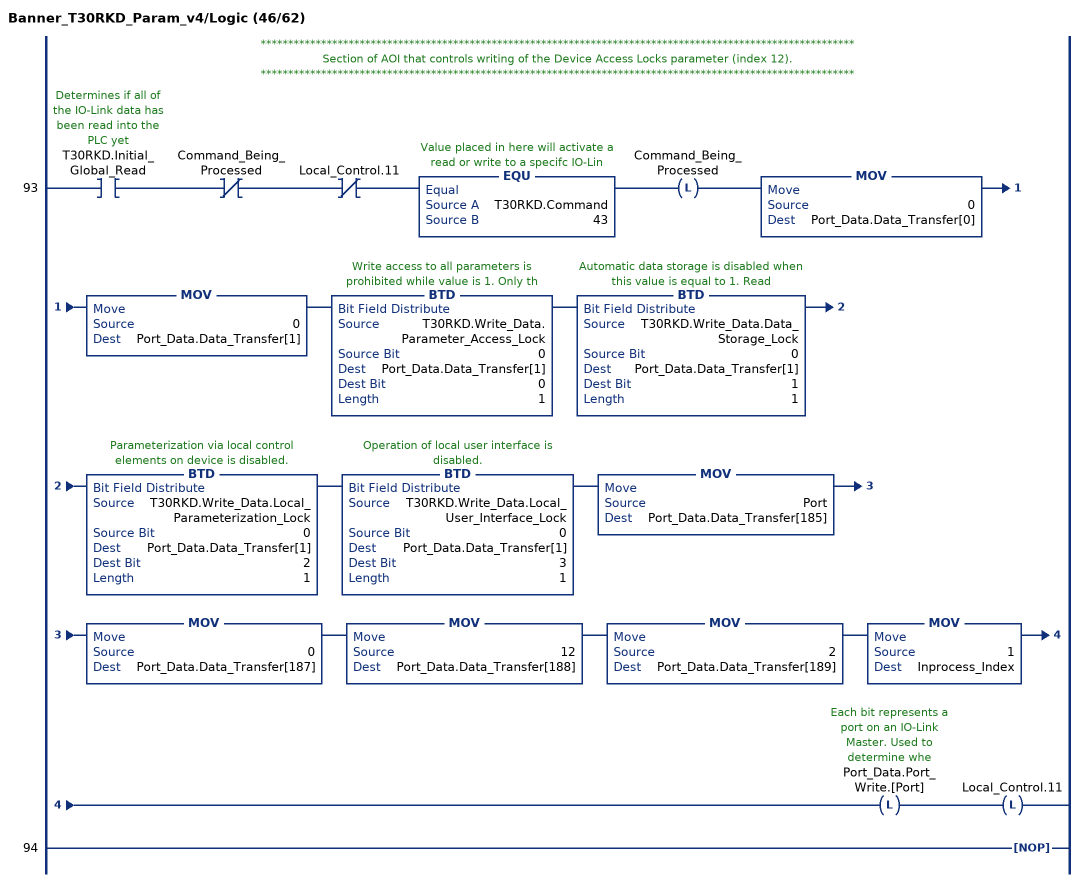
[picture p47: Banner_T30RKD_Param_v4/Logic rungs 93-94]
   // ************************************************************************************************************
   // Section of AOI that controls writing of the Device Access Locks parameter (index 12).
   // ************************************************************************************************************
   93: XIC(T30RKD.Initial_Global_Read)XIO(Command_Being_Processed)XIO(Local_Control.11)EQU(T30RKD.Command,43)OTL(Command_Being_Processed)MOV(0,Port_Data.Data_Transfer[0])MOV(0,Port_Data.Data_Transfer[1])BTD(T30RKD.Write_Data.Parameter_Access_Lock,0,Port_Data.Data_Transfer[1],0,1)BTD(T30RKD.Write_Data.Data_Storage_Lock,0,Port_Data.Data_Transfer[1],1,1)BTD(T30RKD.Write_Data.Local_Parameterization_Lock,0,Port_Data.Data_Transfer[1],2,1)BTD(T30RKD.Write_Data.Local_User_Interface_Lock,0,Port_Data.Data_Transfer[1],3,1)MOV(Port,Port_Data.Data_Transfer[185])MOV(0,Port_Data.Data_Transfer[187])MOV(12,Port_Data.Data_Transfer[188])MOV(2,Port_Data.Data_Transfer[189])MOV(1,Inprocess_Index)OTL(Port_Data.Port_Write.[Port])OTL(Local_Control.11);
   94: NOP();
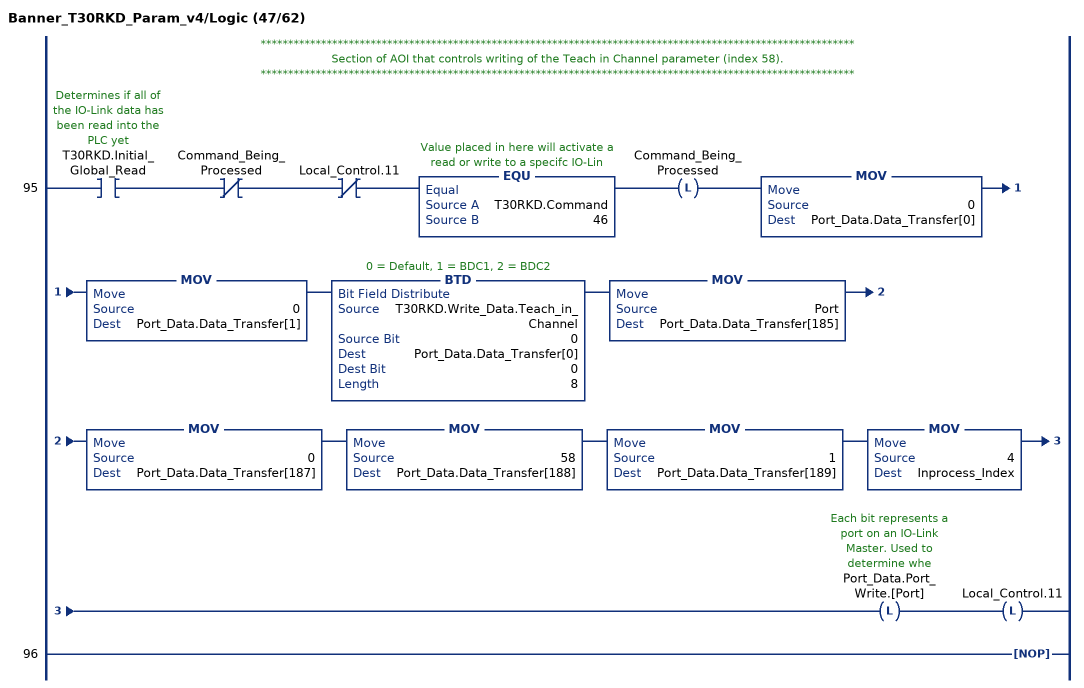
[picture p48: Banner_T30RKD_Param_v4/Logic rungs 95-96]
   // ************************************************************************************************************
   // Section of AOI that controls writing of the Teach in Channel parameter (index 58).
   // ************************************************************************************************************
   95: XIC(T30RKD.Initial_Global_Read)XIO(Command_Being_Processed)XIO(Local_Control.11)EQU(T30RKD.Command,46)OTL(Command_Being_Processed)MOV(0,Port_Data.Data_Transfer[0])MOV(0,Port_Data.Data_Transfer[1])BTD(T30RKD.Write_Data.Teach_in_Channel,0,Port_Data.Data_Transfer[0],0,8)MOV(Port,Port_Data.Data_Transfer[185])MOV(0,Port_Data.Data_Transfer[187])MOV(58,Port_Data.Data_Transfer[188])MOV(1,Port_Data.Data_Transfer[189])MOV(4,Inprocess_Index)OTL(Port_Data.Port_Write.[Port])OTL(Local_Control.11);
   96: NOP();
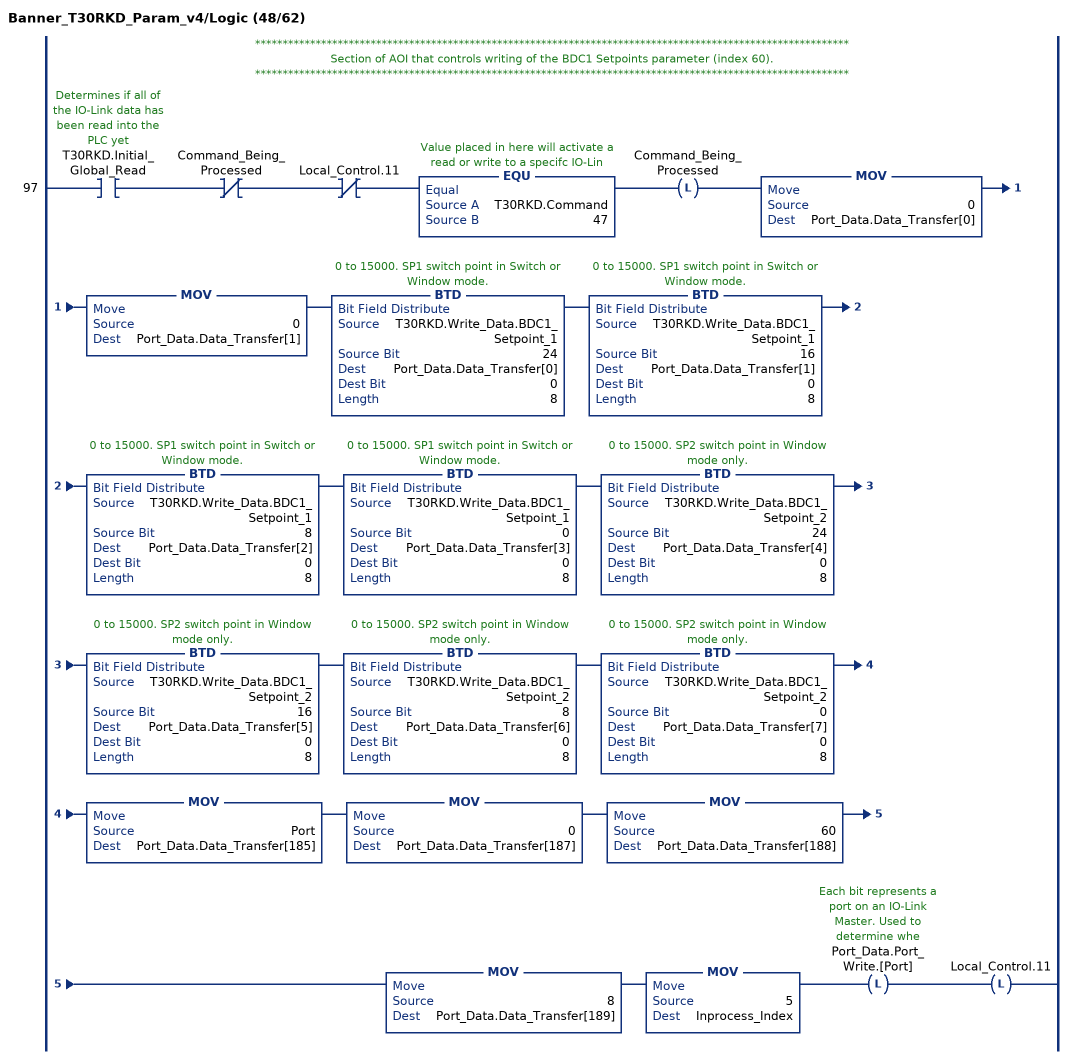
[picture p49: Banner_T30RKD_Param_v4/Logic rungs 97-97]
   // ************************************************************************************************************
   // Section of AOI that controls writing of the BDC1 Setpoints parameter (index 60).
   // ************************************************************************************************************
   97: XIC(T30RKD.Initial_Global_Read)XIO(Command_Being_Processed)XIO(Local_Control.11)EQU(T30RKD.Command,47)OTL(Command_Being_Processed)MOV(0,Port_Data.Data_Transfer[0])MOV(0,Port_Data.Data_Transfer[1])BTD(T30RKD.Write_Data.BDC1_Setpoint_1,24,Port_Data.Data_Transfer[0],0,8)BTD(T30RKD.Write_Data.BDC1_Setpoint_1,16,Port_Data.Data_Transfer[1],0,8)BTD(T30RKD.Write_Data.BDC1_Setpoint_1,8,Port_Data.Data_Transfer[2],0,8)BTD(T30RKD.Write_Data.BDC1_Setpoint_1,0,Port_Data.Data_Transfer[3],0,8)BTD(T30RKD.Write_Data.BDC1_Setpoint_2,24,Port_Data.Data_Transfer[4],0,8)BTD(T30RKD.Write_Data.BDC1_Setpoint_2,16,Port_Data.Data_Transfer[5],0,8)BTD(T30RKD.Write_Data.BDC1_Setpoint_2,8,Port_Data.Data_Transfer[6],0,8)BTD(T30RKD.Write_Data.BDC1_Setpoint_2,0,Port_Data.Data_Transfer[7],0,8)MOV(Port,Port_Data.Data_Transfer[185])MOV(0,Port_Data.Data_Transfer[187])MOV(60,Port_Data.Data_Transfer[188])MOV(8,Port_Data.Data_Transfer[189])MOV(5,Inprocess_Index)OTL(Port_Data.Port_Write.[Port])OTL(Local_Control.11);
(* Logix 5000 AddOnInstructionDefinition export Banner_T30RKD_Param_v4; software revision 32.00; part 3 of 3 *)
(* tags used below, declared in another part *)
   T30RKD : Banner_T30RKD_v3;
   Port_Data : Banner_IOL_Port_v4;
   Port : DINT;
   Local_Control : DINT;
   Command_Being_Processed : BOOL;
   Update_Archive : BOOL;
   Index_Write_Inprocess : DINT;
   Inprocess_Index : DINT;
(* Banner_T30RKD_Param_v4, continued *)

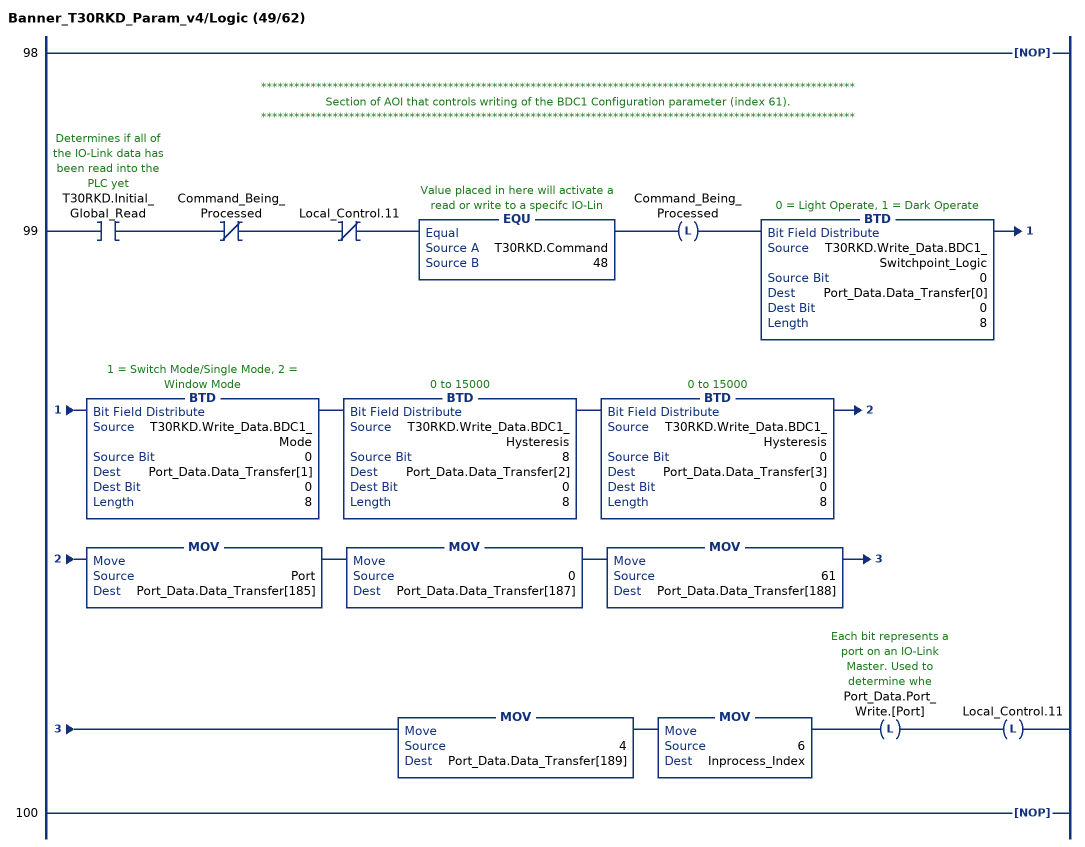
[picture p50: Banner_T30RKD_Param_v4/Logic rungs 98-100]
   98: NOP();
   // ************************************************************************************************************
   // Section of AOI that controls writing of the BDC1 Configuration parameter (index 61).
   // ************************************************************************************************************
   99: XIC(T30RKD.Initial_Global_Read)XIO(Command_Being_Processed)XIO(Local_Control.11)EQU(T30RKD.Command,48)OTL(Command_Being_Processed)BTD(T30RKD.Write_Data.BDC1_Switchpoint_Logic,0,Port_Data.Data_Transfer[0],0,8)BTD(T30RKD.Write_Data.BDC1_Mode,0,Port_Data.Data_Transfer[1],0,8)BTD(T30RKD.Write_Data.BDC1_Hysteresis,8,Port_Data.Data_Transfer[2],0,8)BTD(T30RKD.Write_Data.BDC1_Hysteresis,0,Port_Data.Data_Transfer[3],0,8)MOV(Port,Port_Data.Data_Transfer[185])MOV(0,Port_Data.Data_Transfer[187])MOV(61,Port_Data.Data_Transfer[188])MOV(4,Port_Data.Data_Transfer[189])MOV(6,Inprocess_Index)OTL(Port_Data.Port_Write.[Port])OTL(Local_Control.11);
   100: NOP();
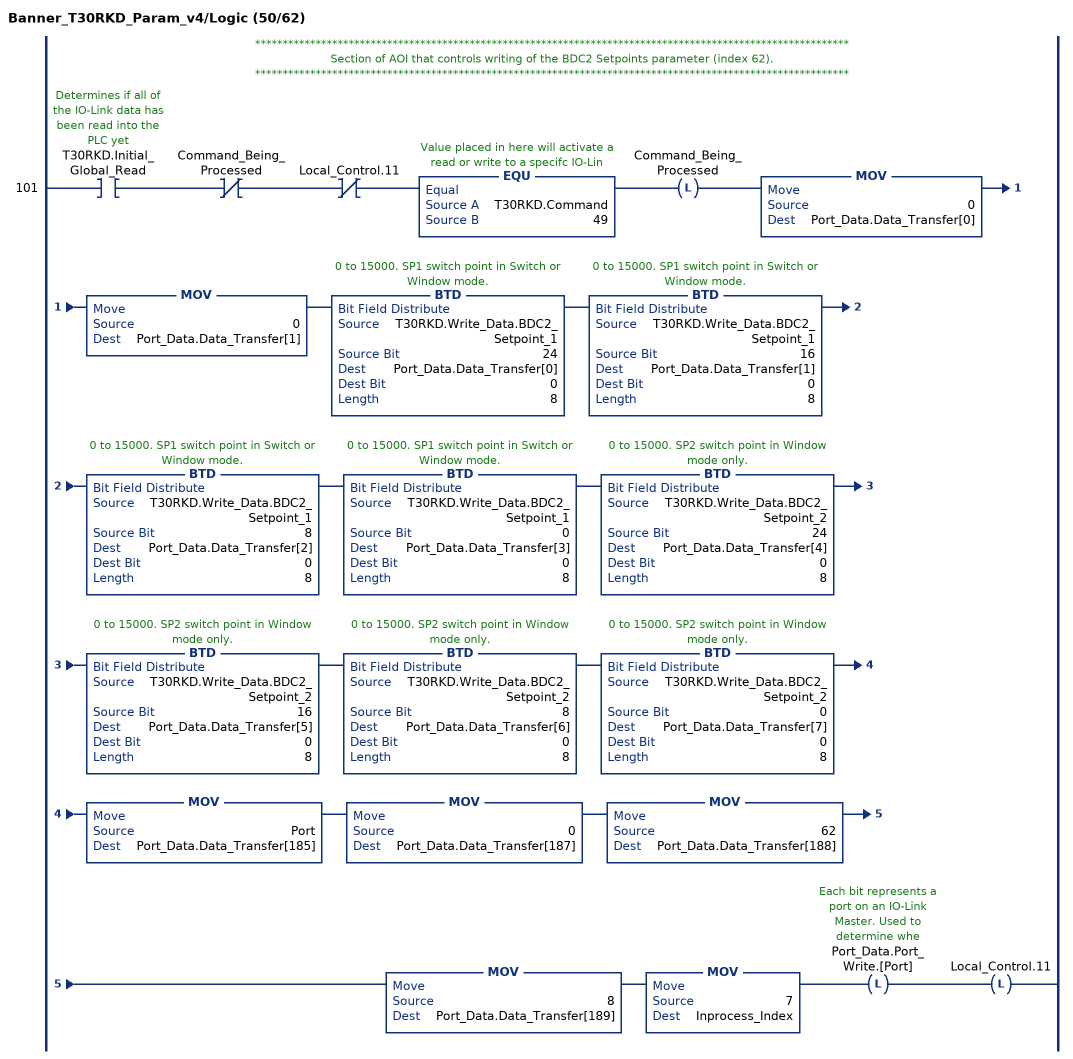
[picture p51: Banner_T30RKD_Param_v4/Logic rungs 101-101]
   // ************************************************************************************************************
   // Section of AOI that controls writing of the BDC2 Setpoints parameter (index 62).
   // ************************************************************************************************************
   101: XIC(T30RKD.Initial_Global_Read)XIO(Command_Being_Processed)XIO(Local_Control.11)EQU(T30RKD.Command,49)OTL(Command_Being_Processed)MOV(0,Port_Data.Data_Transfer[0])MOV(0,Port_Data.Data_Transfer[1])BTD(T30RKD.Write_Data.BDC2_Setpoint_1,24,Port_Data.Data_Transfer[0],0,8)BTD(T30RKD.Write_Data.BDC2_Setpoint_1,16,Port_Data.Data_Transfer[1],0,8)BTD(T30RKD.Write_Data.BDC2_Setpoint_1,8,Port_Data.Data_Transfer[2],0,8)BTD(T30RKD.Write_Data.BDC2_Setpoint_1,0,Port_Data.Data_Transfer[3],0,8)BTD(T30RKD.Write_Data.BDC2_Setpoint_2,24,Port_Data.Data_Transfer[4],0,8)BTD(T30RKD.Write_Data.BDC2_Setpoint_2,16,Port_Data.Data_Transfer[5],0,8)BTD(T30RKD.Write_Data.BDC2_Setpoint_2,8,Port_Data.Data_Transfer[6],0,8)BTD(T30RKD.Write_Data.BDC2_Setpoint_2,0,Port_Data.Data_Transfer[7],0,8)MOV(Port,Port_Data.Data_Transfer[185])MOV(0,Port_Data.Data_Transfer[187])MOV(62,Port_Data.Data_Transfer[188])MOV(8,Port_Data.Data_Transfer[189])MOV(7,Inprocess_Index)OTL(Port_Data.Port_Write.[Port])OTL(Local_Control.11);
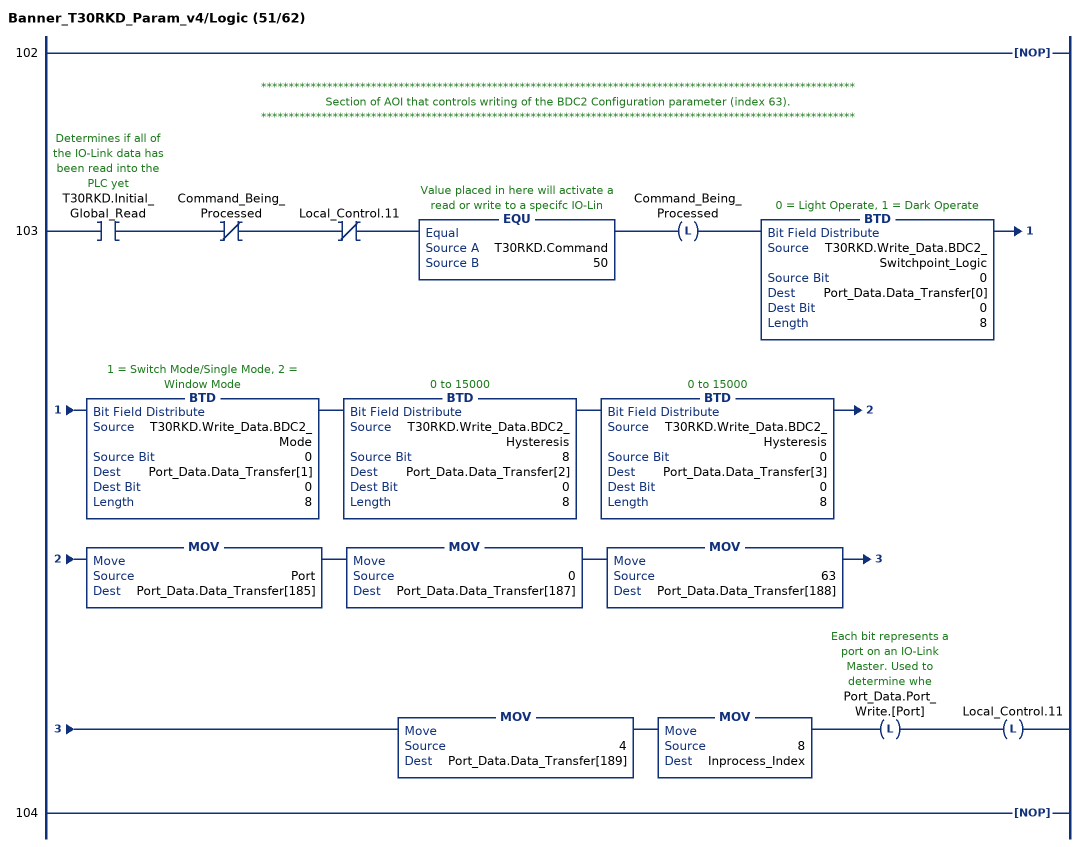
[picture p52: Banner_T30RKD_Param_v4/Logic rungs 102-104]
   102: NOP();
   // ************************************************************************************************************
   // Section of AOI that controls writing of the BDC2 Configuration parameter (index 63).
   // ************************************************************************************************************
   103: XIC(T30RKD.Initial_Global_Read)XIO(Command_Being_Processed)XIO(Local_Control.11)EQU(T30RKD.Command,50)OTL(Command_Being_Processed)BTD(T30RKD.Write_Data.BDC2_Switchpoint_Logic,0,Port_Data.Data_Transfer[0],0,8)BTD(T30RKD.Write_Data.BDC2_Mode,0,Port_Data.Data_Transfer[1],0,8)BTD(T30RKD.Write_Data.BDC2_Hysteresis,8,Port_Data.Data_Transfer[2],0,8)BTD(T30RKD.Write_Data.BDC2_Hysteresis,0,Port_Data.Data_Transfer[3],0,8)MOV(Port,Port_Data.Data_Transfer[185])MOV(0,Port_Data.Data_Transfer[187])MOV(63,Port_Data.Data_Transfer[188])MOV(4,Port_Data.Data_Transfer[189])MOV(8,Inprocess_Index)OTL(Port_Data.Port_Write.[Port])OTL(Local_Control.11);
   104: NOP();
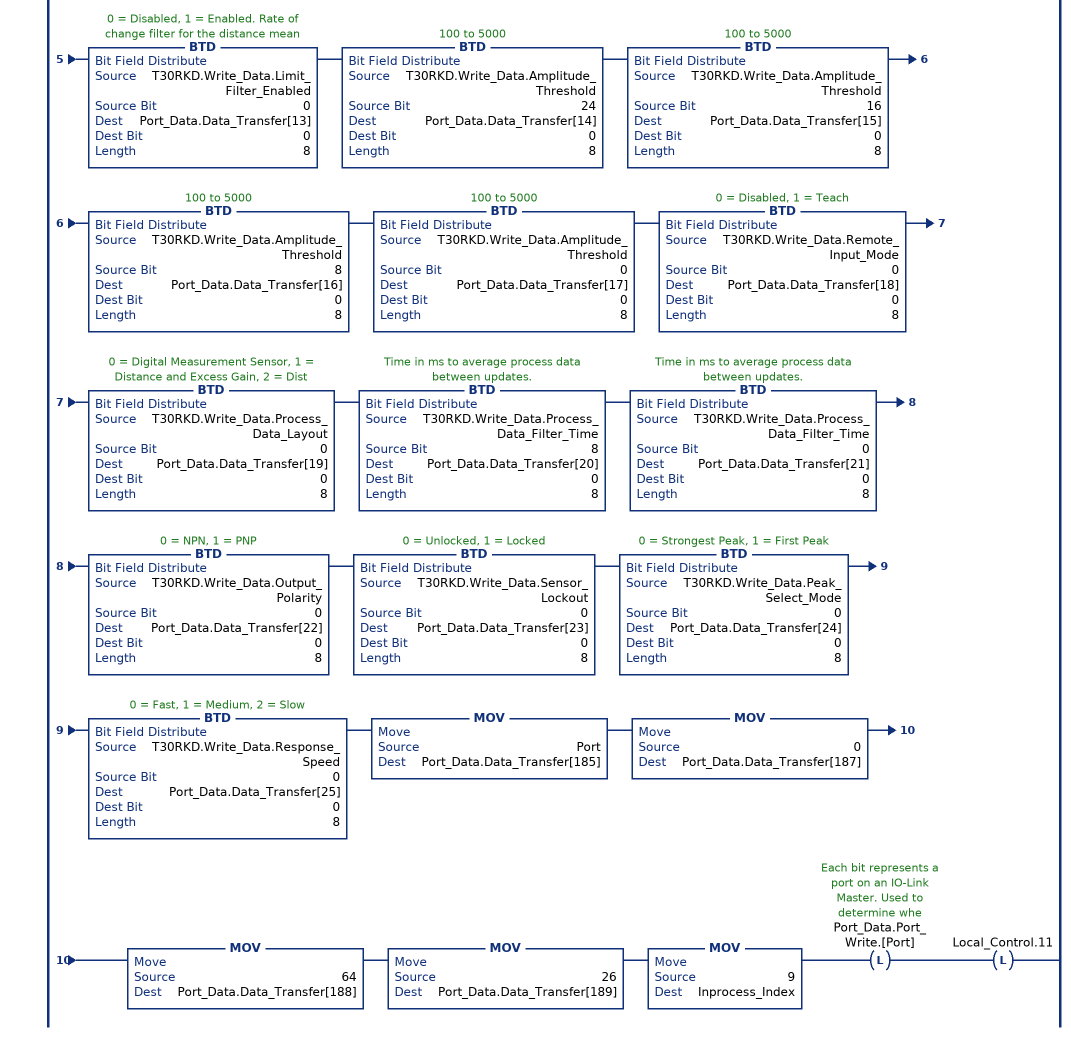
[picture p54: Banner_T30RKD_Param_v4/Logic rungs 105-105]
   // ************************************************************************************************************
   // Section of AOI that controls writing of the Configuration parameter (index 64).
   // ************************************************************************************************************
   105: XIC(T30RKD.Initial_Global_Read)XIO(Command_Being_Processed)XIO(Local_Control.11)EQU(T30RKD.Command,51)OTL(Command_Being_Processed)BTD(T30RKD.Write_Data.Secondary_Output_Mode,0,Port_Data.Data_Transfer[0],0,8)BTD(T30RKD.Write_Data.Limit_Filter_Negative_Distance,24,Port_Data.Data_Transfer[1],0,8)BTD(T30RKD.Write_Data.Limit_Filter_Negative_Distance,16,Port_Data.Data_Transfer[2],0,8)BTD(T30RKD.Write_Data.Limit_Filter_Negative_Distance,8,Port_Data.Data_Transfer[3],0,8)BTD(T30RKD.Write_Data.Limit_Filter_Negative_Distance,0,Port_Data.Data_Transfer[4],0,8)BTD(T30RKD.Write_Data.Limit_Filter_Positive_Distance,24,Port_Data.Data_Transfer[5],0,8)BTD(T30RKD.Write_Data.Limit_Filter_Positive_Distance,16,Port_Data.Data_Transfer[6],0,8)BTD(T30RKD.Write_Data.Limit_Filter_Positive_Distance,8,Port_Data.Data_Transfer[7],0,8)BTD(T30RKD.Write_Data.Limit_Filter_Positive_Distance,0,Port_Data.Data_Transfer[8],0,8)BTD(T30RKD.Write_Data.Limit_Filter_Hold_Time,24,Port_Data.Data_Transfer[9],0,8)BTD(T30RKD.Write_Data.Limit_Filter_Hold_Time,16,Port_Data.Data_Transfer[10],0,8)BTD(T30RKD.Write_Data.Limit_Filter_Hold_Time,8,Port_Data.Data_Transfer[11],0,8)BTD(T30RKD.Write_Data.Limit_Filter_Hold_Time,0,Port_Data.Data_Transfer[12],0,8)BTD(T30RKD.Write_Data.Limit_Filter_Enabled,0,Port_Data.Data_Transfer[13],0,8)BTD(T30RKD.Write_Data.Amplitude_Threshold,24,Port_Data.Data_Transfer[14],0,8)BTD(T30RKD.Write_Data.Amplitude_Threshold,16,Port_Data.Data_Transfer[15],0,8)BTD(T30RKD.Write_Data.Amplitude_Threshold,8,Port_Data.Data_Transfer[16],0,8)BTD(T30RKD.Write_Data.Amplitude_Threshold,0,Port_Data.Data_Transfer[17],0,8)BTD(T30RKD.Write_Data.Remote_Input_Mode,0,Port_Data.Data_Transfer[18],0,8)BTD(T30RKD.Write_Data.Process_Data_Layout,0,Port_Data.Data_Transfer[19],0,8)BTD(T30RKD.Write_Data.Process_Data_Filter_Time,8,Port_Data.Data_Transfer[20],0,8)BTD(T30RKD.Write_Data.Process_Data_Filter_Time,0,Port_Data.Data_Transfer[21],0,8)BTD(T30RKD.Write_Data.Output_Polarity,0,Port_Data.Data_Transfer[22],0,8)BTD(T30RKD.Write_Data.Sensor_Lockout,0,Port_Data.Data_Transfer[23],0,8)BTD(T30RKD.Write_Data.Peak_Select_Mode,0,Port_Data.Data_Transfer[24],0,8)BTD(T30RKD.Write_Data.Response_Speed,0,Port_Data.Data_Transfer[25],0,8)MOV(Port,Port_Data.Data_Transfer[185])MOV(0,Port_Data.Data_Transfer[187])MOV(64,Port_Data.Data_Transfer[188])MOV(26,Port_Data.Data_Transfer[189])MOV(9,Inprocess_Index)OTL(Port_Data.Port_Write.[Port])OTL(Local_Control.11);
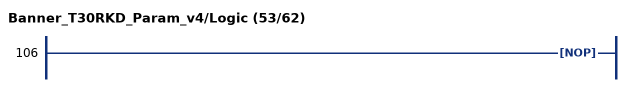
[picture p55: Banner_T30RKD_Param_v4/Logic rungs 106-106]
   106: NOP();
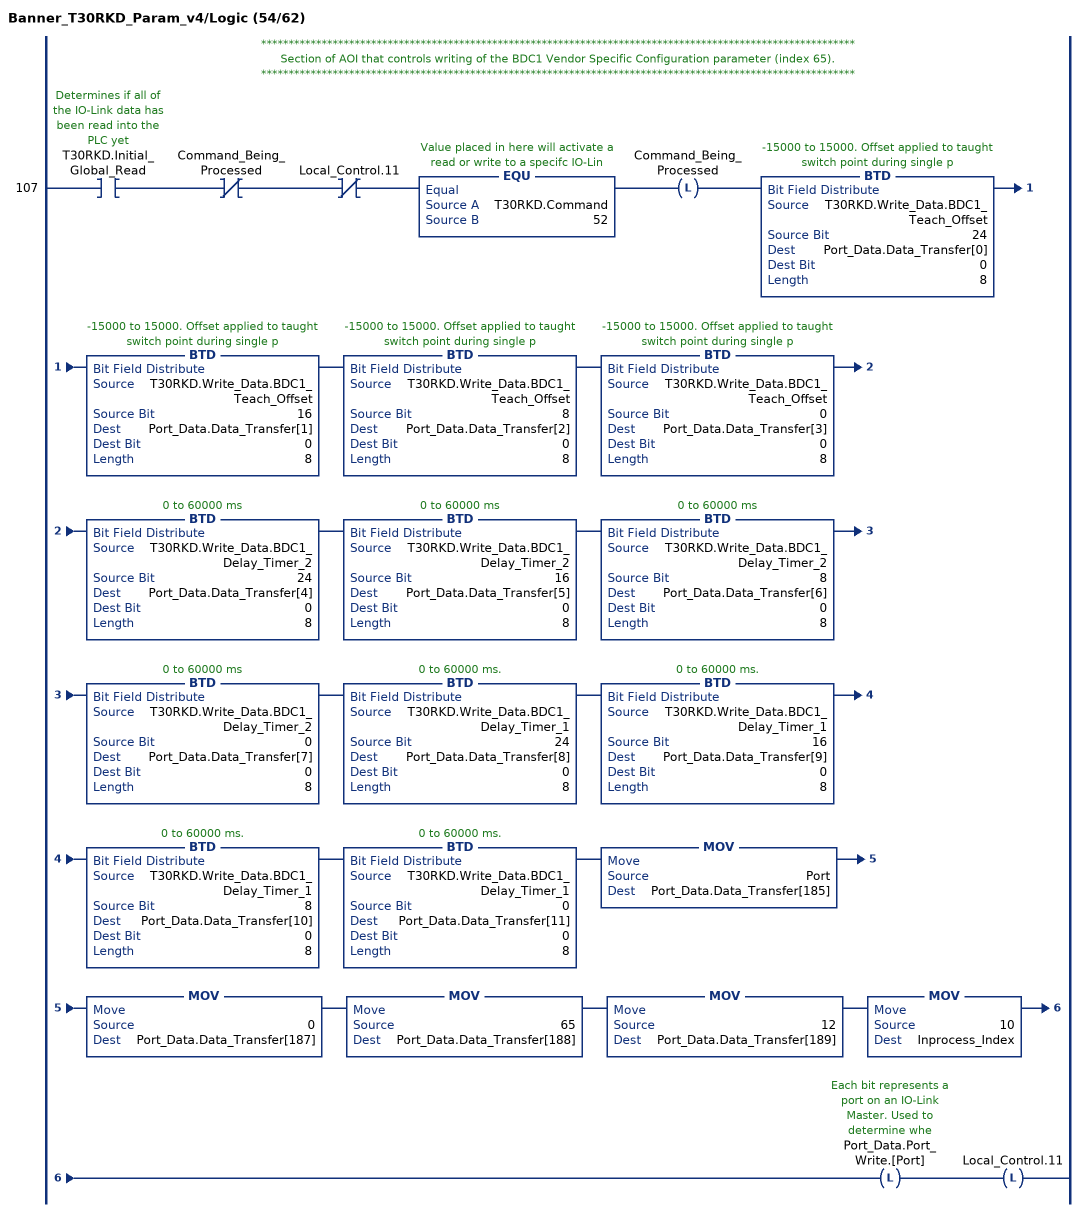
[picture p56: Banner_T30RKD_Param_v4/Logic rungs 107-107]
   // ************************************************************************************************************
   // Section of AOI that controls writing of the BDC1 Vendor Specific Configuration parameter (index 65).
   // ************************************************************************************************************
   107: XIC(T30RKD.Initial_Global_Read)XIO(Command_Being_Processed)XIO(Local_Control.11)EQU(T30RKD.Command,52)OTL(Command_Being_Processed)BTD(T30RKD.Write_Data.BDC1_Teach_Offset,24,Port_Data.Data_Transfer[0],0,8)BTD(T30RKD.Write_Data.BDC1_Teach_Offset,16,Port_Data.Data_Transfer[1],0,8)BTD(T30RKD.Write_Data.BDC1_Teach_Offset,8,Port_Data.Data_Transfer[2],0,8)BTD(T30RKD.Write_Data.BDC1_Teach_Offset,0,Port_Data.Data_Transfer[3],0,8)BTD(T30RKD.Write_Data.BDC1_Delay_Timer_2,24,Port_Data.Data_Transfer[4],0,8)BTD(T30RKD.Write_Data.BDC1_Delay_Timer_2,16,Port_Data.Data_Transfer[5],0,8)BTD(T30RKD.Write_Data.BDC1_Delay_Timer_2,8,Port_Data.Data_Transfer[6],0,8)BTD(T30RKD.Write_Data.BDC1_Delay_Timer_2,0,Port_Data.Data_Transfer[7],0,8)BTD(T30RKD.Write_Data.BDC1_Delay_Timer_1,24,Port_Data.Data_Transfer[8],0,8)BTD(T30RKD.Write_Data.BDC1_Delay_Timer_1,16,Port_Data.Data_Transfer[9],0,8)BTD(T30RKD.Write_Data.BDC1_Delay_Timer_1,8,Port_Data.Data_Transfer[10],0,8)BTD(T30RKD.Write_Data.BDC1_Delay_Timer_1,0,Port_Data.Data_Transfer[11],0,8)MOV(Port,Port_Data.Data_Transfer[185])MOV(0,Port_Data.Data_Transfer[187])MOV(65,Port_Data.Data_Transfer[188])MOV(12,Port_Data.Data_Transfer[189])MOV(10,Inprocess_Index)OTL(Port_Data.Port_Write.[Port])OTL(Local_Control.11);
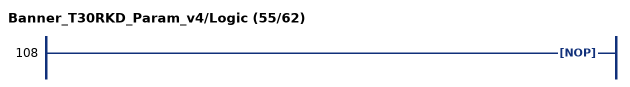
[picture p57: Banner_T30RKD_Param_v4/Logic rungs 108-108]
   108: NOP();
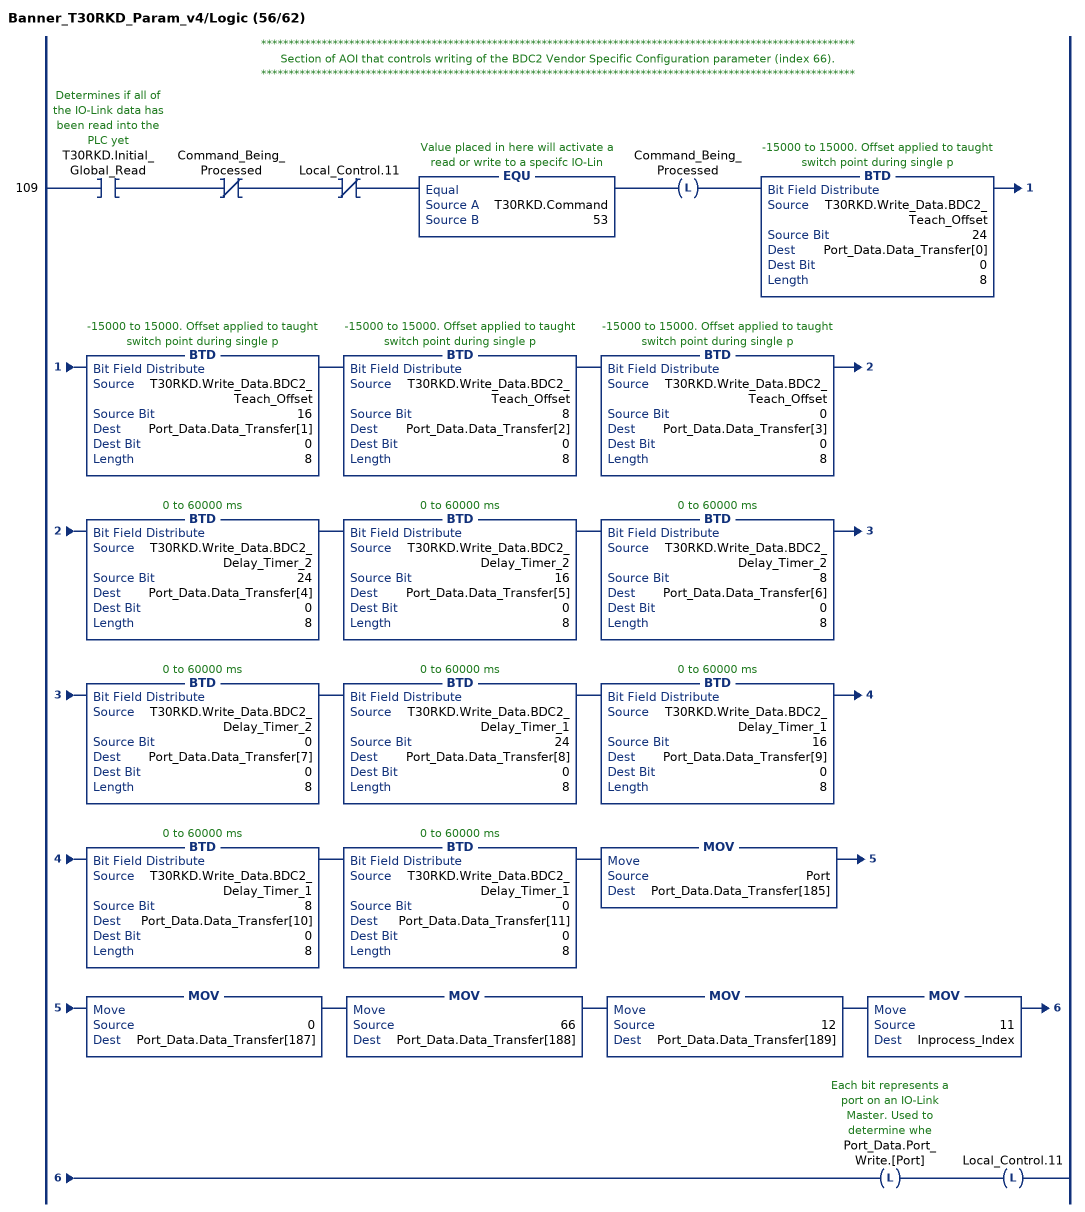
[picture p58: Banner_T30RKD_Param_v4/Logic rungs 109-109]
   // ************************************************************************************************************
   // Section of AOI that controls writing of the BDC2 Vendor Specific Configuration parameter (index 66).
   // ************************************************************************************************************
   109: XIC(T30RKD.Initial_Global_Read)XIO(Command_Being_Processed)XIO(Local_Control.11)EQU(T30RKD.Command,53)OTL(Command_Being_Processed)BTD(T30RKD.Write_Data.BDC2_Teach_Offset,24,Port_Data.Data_Transfer[0],0,8)BTD(T30RKD.Write_Data.BDC2_Teach_Offset,16,Port_Data.Data_Transfer[1],0,8)BTD(T30RKD.Write_Data.BDC2_Teach_Offset,8,Port_Data.Data_Transfer[2],0,8)BTD(T30RKD.Write_Data.BDC2_Teach_Offset,0,Port_Data.Data_Transfer[3],0,8)BTD(T30RKD.Write_Data.BDC2_Delay_Timer_2,24,Port_Data.Data_Transfer[4],0,8)BTD(T30RKD.Write_Data.BDC2_Delay_Timer_2,16,Port_Data.Data_Transfer[5],0,8)BTD(T30RKD.Write_Data.BDC2_Delay_Timer_2,8,Port_Data.Data_Transfer[6],0,8)BTD(T30RKD.Write_Data.BDC2_Delay_Timer_2,0,Port_Data.Data_Transfer[7],0,8)BTD(T30RKD.Write_Data.BDC2_Delay_Timer_1,24,Port_Data.Data_Transfer[8],0,8)BTD(T30RKD.Write_Data.BDC2_Delay_Timer_1,16,Port_Data.Data_Transfer[9],0,8)BTD(T30RKD.Write_Data.BDC2_Delay_Timer_1,8,Port_Data.Data_Transfer[10],0,8)BTD(T30RKD.Write_Data.BDC2_Delay_Timer_1,0,Port_Data.Data_Transfer[11],0,8)MOV(Port,Port_Data.Data_Transfer[185])MOV(0,Port_Data.Data_Transfer[187])MOV(66,Port_Data.Data_Transfer[188])MOV(12,Port_Data.Data_Transfer[189])MOV(11,Inprocess_Index)OTL(Port_Data.Port_Write.[Port])OTL(Local_Control.11);
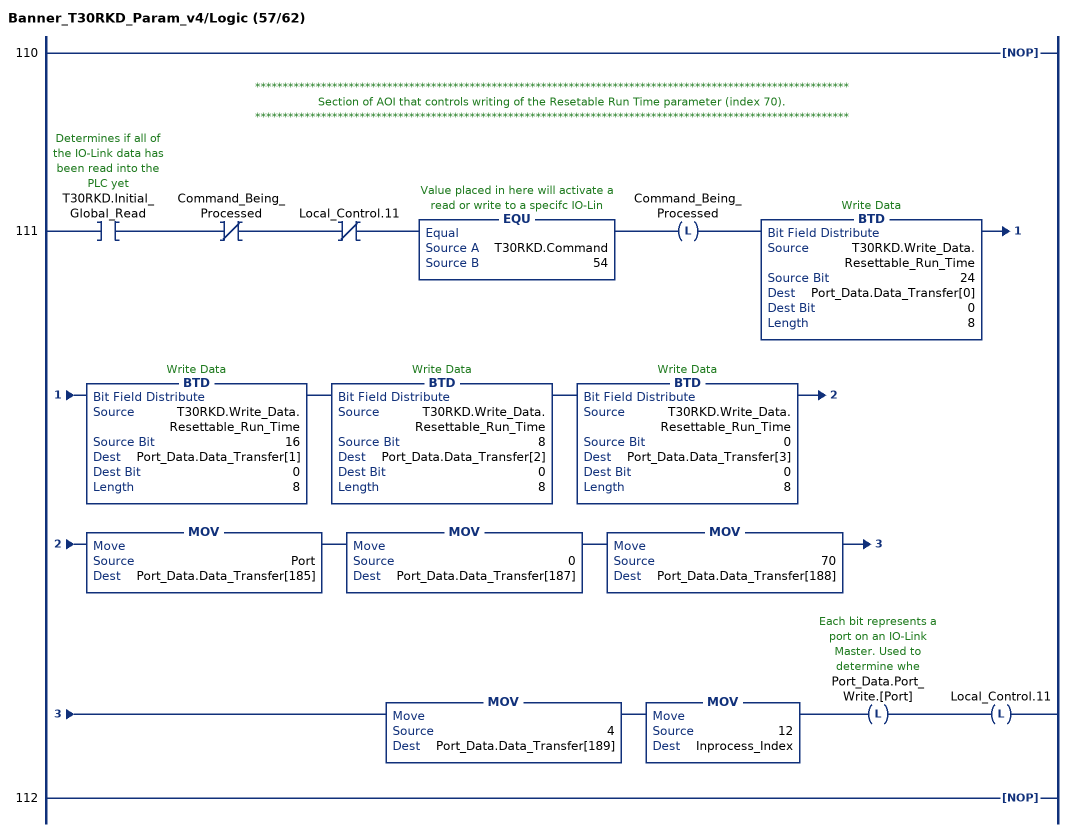
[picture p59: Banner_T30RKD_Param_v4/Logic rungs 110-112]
   110: NOP();
   // ************************************************************************************************************
   // Section of AOI that controls writing of the Resetable Run Time parameter (index 70).
   // ************************************************************************************************************
   111: XIC(T30RKD.Initial_Global_Read)XIO(Command_Being_Processed)XIO(Local_Control.11)EQU(T30RKD.Command,54)OTL(Command_Being_Processed)BTD(T30RKD.Write_Data.Resettable_Run_Time,24,Port_Data.Data_Transfer[0],0,8)BTD(T30RKD.Write_Data.Resettable_Run_Time,16,Port_Data.Data_Transfer[1],0,8)BTD(T30RKD.Write_Data.Resettable_Run_Time,8,Port_Data.Data_Transfer[2],0,8)BTD(T30RKD.Write_Data.Resettable_Run_Time,0,Port_Data.Data_Transfer[3],0,8)MOV(Port,Port_Data.Data_Transfer[185])MOV(0,Port_Data.Data_Transfer[187])MOV(70,Port_Data.Data_Transfer[188])MOV(4,Port_Data.Data_Transfer[189])MOV(12,Inprocess_Index)OTL(Port_Data.Port_Write.[Port])OTL(Local_Control.11);
   112: NOP();
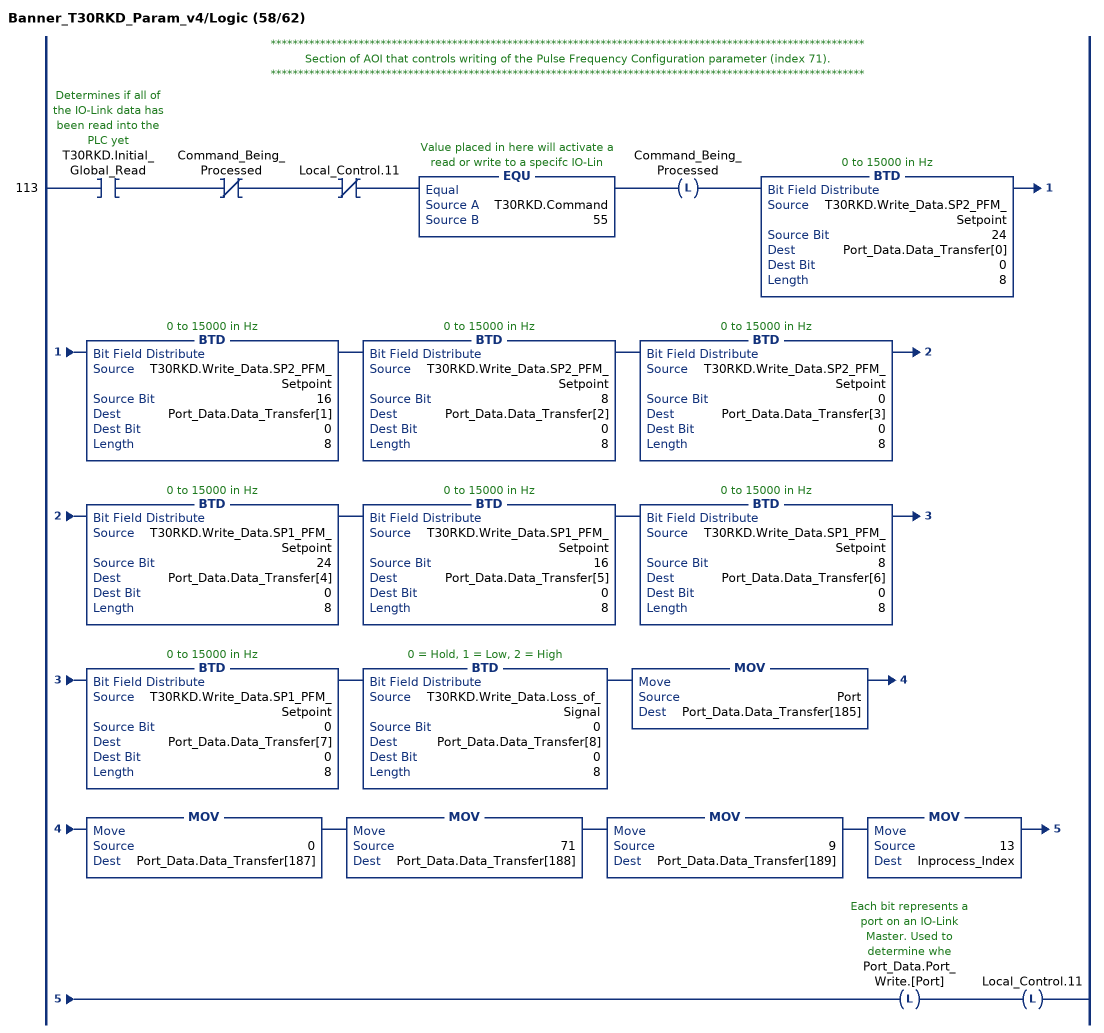
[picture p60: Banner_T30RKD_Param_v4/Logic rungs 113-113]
   // ************************************************************************************************************
   // Section of AOI that controls writing of the Pulse Frequency Configuration parameter (index 71).
   // ************************************************************************************************************
   113: XIC(T30RKD.Initial_Global_Read)XIO(Command_Being_Processed)XIO(Local_Control.11)EQU(T30RKD.Command,55)OTL(Command_Being_Processed)BTD(T30RKD.Write_Data.SP2_PFM_Setpoint,24,Port_Data.Data_Transfer[0],0,8)BTD(T30RKD.Write_Data.SP2_PFM_Setpoint,16,Port_Data.Data_Transfer[1],0,8)BTD(T30RKD.Write_Data.SP2_PFM_Setpoint,8,Port_Data.Data_Transfer[2],0,8)BTD(T30RKD.Write_Data.SP2_PFM_Setpoint,0,Port_Data.Data_Transfer[3],0,8)BTD(T30RKD.Write_Data.SP1_PFM_Setpoint,24,Port_Data.Data_Transfer[4],0,8)BTD(T30RKD.Write_Data.SP1_PFM_Setpoint,16,Port_Data.Data_Transfer[5],0,8)BTD(T30RKD.Write_Data.SP1_PFM_Setpoint,8,Port_Data.Data_Transfer[6],0,8)BTD(T30RKD.Write_Data.SP1_PFM_Setpoint,0,Port_Data.Data_Transfer[7],0,8)BTD(T30RKD.Write_Data.Loss_of_Signal,0,Port_Data.Data_Transfer[8],0,8)MOV(Port,Port_Data.Data_Transfer[185])MOV(0,Port_Data.Data_Transfer[187])MOV(71,Port_Data.Data_Transfer[188])MOV(9,Port_Data.Data_Transfer[189])MOV(13,Inprocess_Index)OTL(Port_Data.Port_Write.[Port])OTL(Local_Control.11);
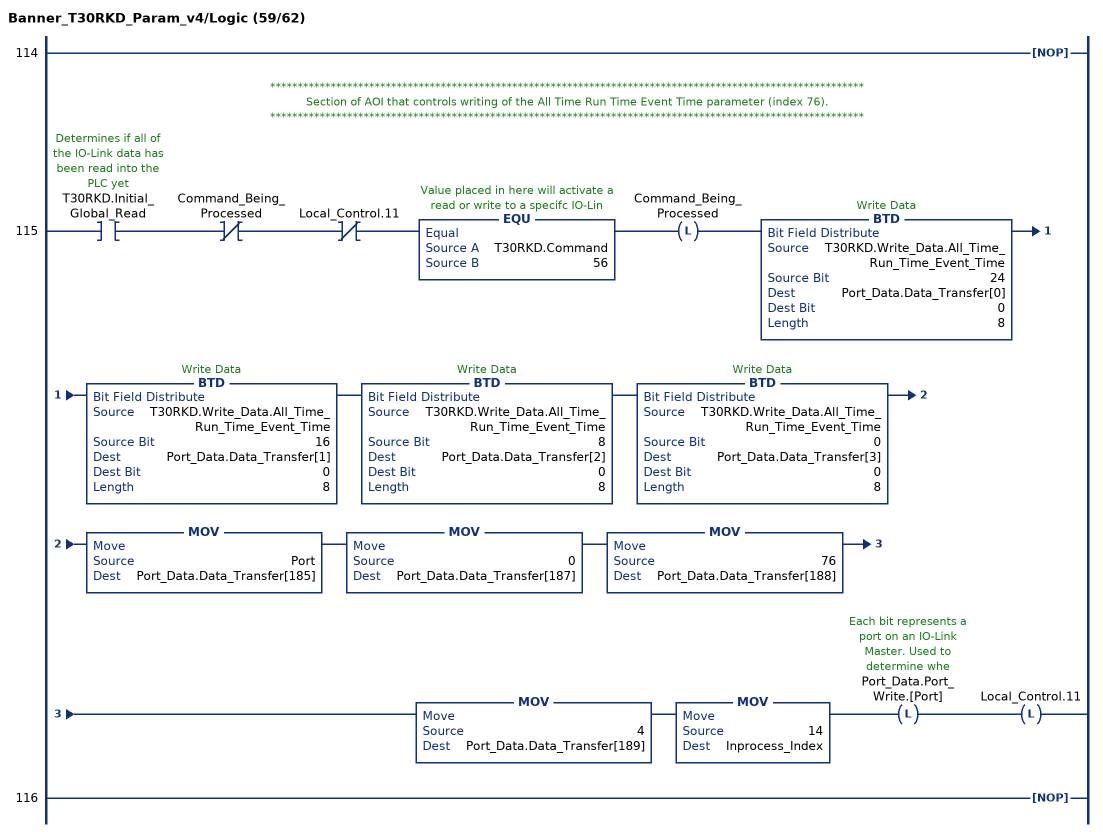
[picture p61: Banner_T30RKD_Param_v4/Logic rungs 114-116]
   114: NOP();
   // ************************************************************************************************************
   // Section of AOI that controls writing of the All Time Run Time Event Time parameter (index 76).
   // ************************************************************************************************************
   115: XIC(T30RKD.Initial_Global_Read)XIO(Command_Being_Processed)XIO(Local_Control.11)EQU(T30RKD.Command,56)OTL(Command_Being_Processed)BTD(T30RKD.Write_Data.All_Time_Run_Time_Event_Time,24,Port_Data.Data_Transfer[0],0,8)BTD(T30RKD.Write_Data.All_Time_Run_Time_Event_Time,16,Port_Data.Data_Transfer[1],0,8)BTD(T30RKD.Write_Data.All_Time_Run_Time_Event_Time,8,Port_Data.Data_Transfer[2],0,8)BTD(T30RKD.Write_Data.All_Time_Run_Time_Event_Time,0,Port_Data.Data_Transfer[3],0,8)MOV(Port,Port_Data.Data_Transfer[185])MOV(0,Port_Data.Data_Transfer[187])MOV(76,Port_Data.Data_Transfer[188])MOV(4,Port_Data.Data_Transfer[189])MOV(14,Inprocess_Index)OTL(Port_Data.Port_Write.[Port])OTL(Local_Control.11);
   116: NOP();
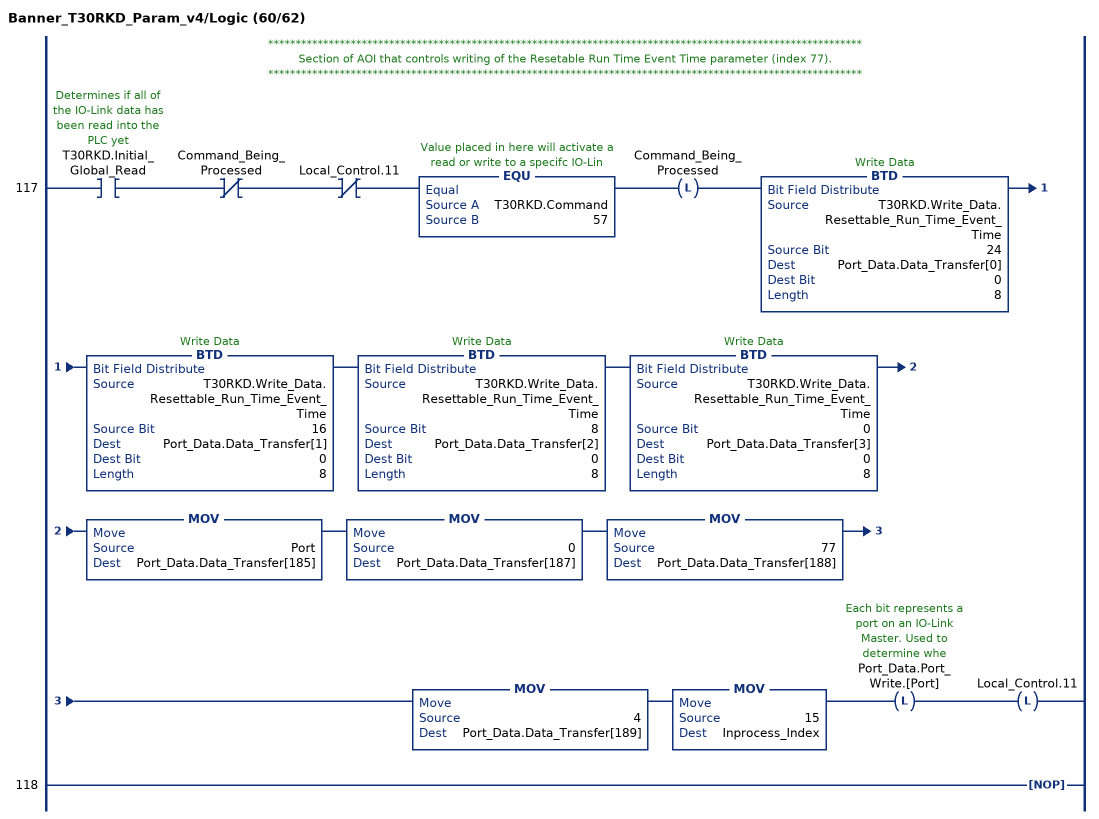
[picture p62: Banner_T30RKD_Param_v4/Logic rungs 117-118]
   // ************************************************************************************************************
   // Section of AOI that controls writing of the Resetable Run Time Event Time parameter (index 77).
   // ************************************************************************************************************
   117: XIC(T30RKD.Initial_Global_Read)XIO(Command_Being_Processed)XIO(Local_Control.11)EQU(T30RKD.Command,57)OTL(Command_Being_Processed)BTD(T30RKD.Write_Data.Resettable_Run_Time_Event_Time,24,Port_Data.Data_Transfer[0],0,8)BTD(T30RKD.Write_Data.Resettable_Run_Time_Event_Time,16,Port_Data.Data_Transfer[1],0,8)BTD(T30RKD.Write_Data.Resettable_Run_Time_Event_Time,8,Port_Data.Data_Transfer[2],0,8)BTD(T30RKD.Write_Data.Resettable_Run_Time_Event_Time,0,Port_Data.Data_Transfer[3],0,8)MOV(Port,Port_Data.Data_Transfer[185])MOV(0,Port_Data.Data_Transfer[187])MOV(77,Port_Data.Data_Transfer[188])MOV(4,Port_Data.Data_Transfer[189])MOV(15,Inprocess_Index)OTL(Port_Data.Port_Write.[Port])OTL(Local_Control.11);
   118: NOP();
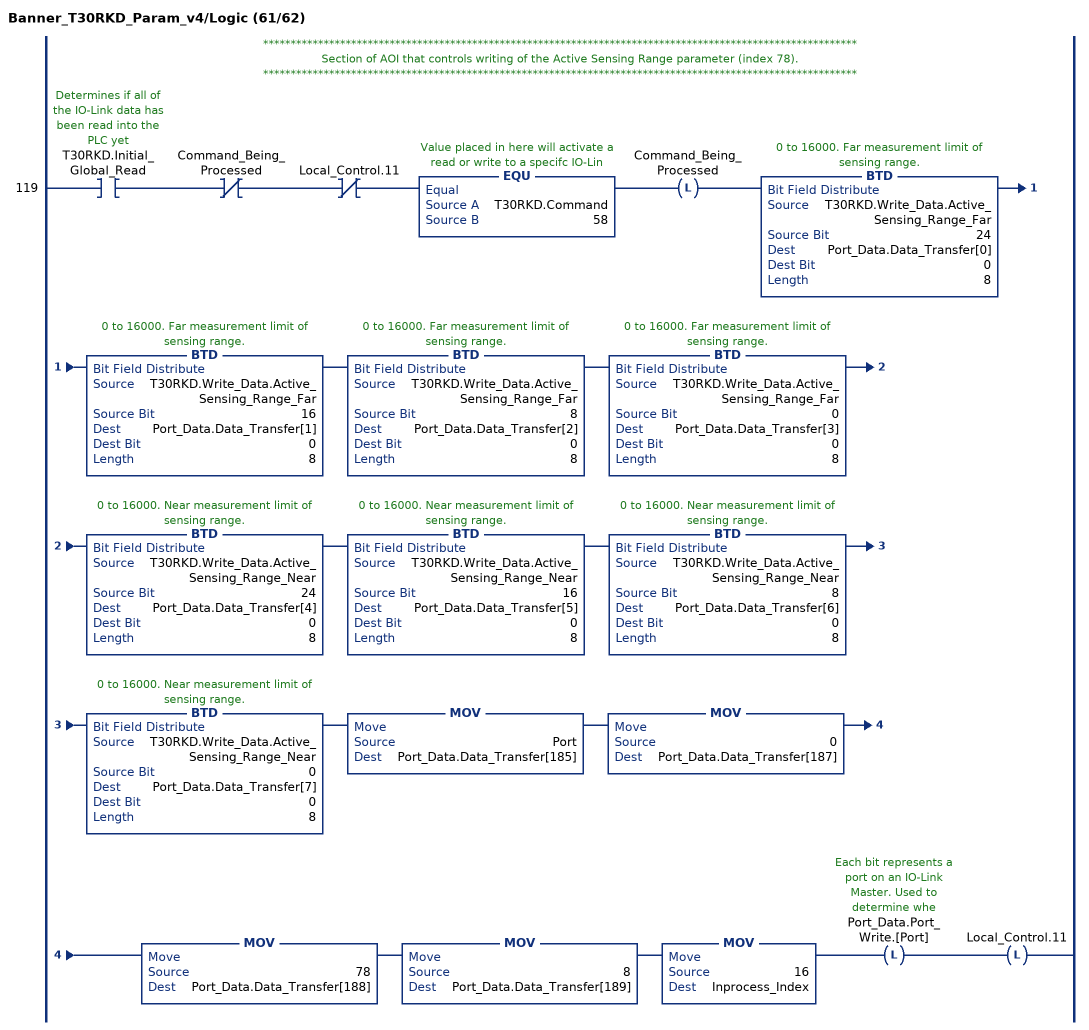
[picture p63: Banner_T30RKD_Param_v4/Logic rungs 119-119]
   // ************************************************************************************************************
   // Section of AOI that controls writing of the Active Sensing Range parameter (index 78).
   // ************************************************************************************************************
   119: XIC(T30RKD.Initial_Global_Read)XIO(Command_Being_Processed)XIO(Local_Control.11)EQU(T30RKD.Command,58)OTL(Command_Being_Processed)BTD(T30RKD.Write_Data.Active_Sensing_Range_Far,24,Port_Data.Data_Transfer[0],0,8)BTD(T30RKD.Write_Data.Active_Sensing_Range_Far,16,Port_Data.Data_Transfer[1],0,8)BTD(T30RKD.Write_Data.Active_Sensing_Range_Far,8,Port_Data.Data_Transfer[2],0,8)BTD(T30RKD.Write_Data.Active_Sensing_Range_Far,0,Port_Data.Data_Transfer[3],0,8)BTD(T30RKD.Write_Data.Active_Sensing_Range_Near,24,Port_Data.Data_Transfer[4],0,8)BTD(T30RKD.Write_Data.Active_Sensing_Range_Near,16,Port_Data.Data_Transfer[5],0,8)BTD(T30RKD.Write_Data.Active_Sensing_Range_Near,8,Port_Data.Data_Transfer[6],0,8)BTD(T30RKD.Write_Data.Active_Sensing_Range_Near,0,Port_Data.Data_Transfer[7],0,8)MOV(Port,Port_Data.Data_Transfer[185])MOV(0,Port_Data.Data_Transfer[187])MOV(78,Port_Data.Data_Transfer[188])MOV(8,Port_Data.Data_Transfer[189])MOV(16,Inprocess_Index)OTL(Port_Data.Port_Write.[Port])OTL(Local_Control.11);
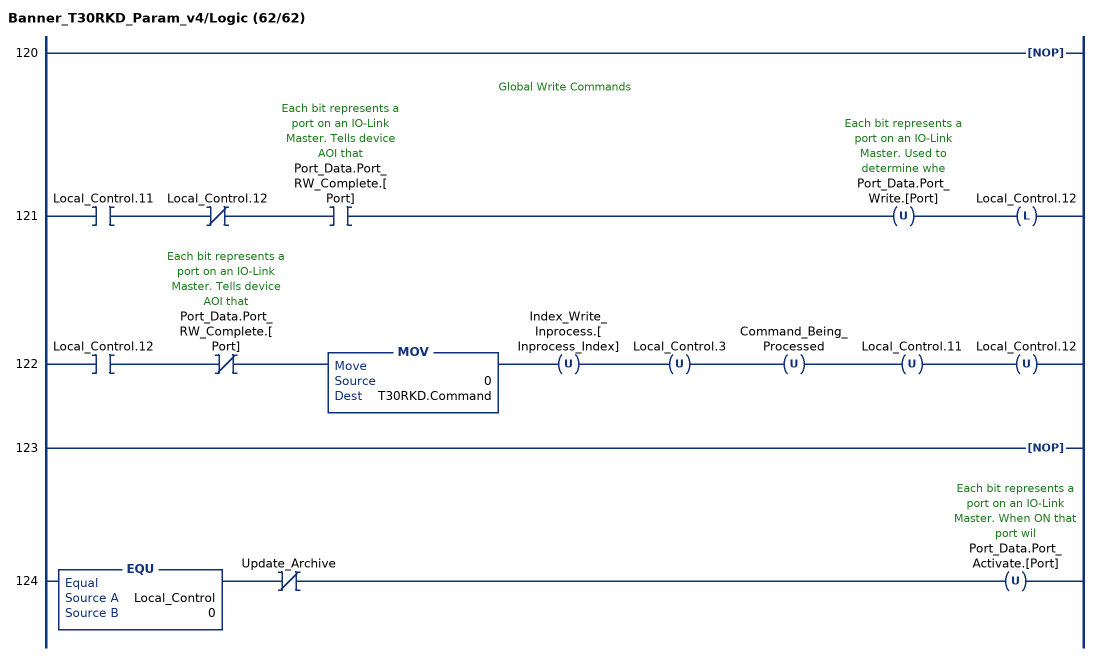
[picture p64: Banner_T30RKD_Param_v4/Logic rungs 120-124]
   120: NOP();
   // Global Write Commands
   121: XIC(Local_Control.11)XIO(Local_Control.12)XIC(Port_Data.Port_RW_Complete.[Port])OTU(Port_Data.Port_Write.[Port])OTL(Local_Control.12);
   122: XIC(Local_Control.12)XIO(Port_Data.Port_RW_Complete.[Port])MOV(0,T30RKD.Command)OTU(Index_Write_Inprocess.[Inprocess_Index])OTU(Local_Control.3)OTU(Command_Being_Processed)OTU(Local_Control.11)OTU(Local_Control.12);
   123: NOP();
   124: EQU(Local_Control,0)XIO(Update_Archive)OTU(Port_Data.Port_Activate.[Port]);
END_ROUTINE
END_ADD_ON_INSTRUCTION
